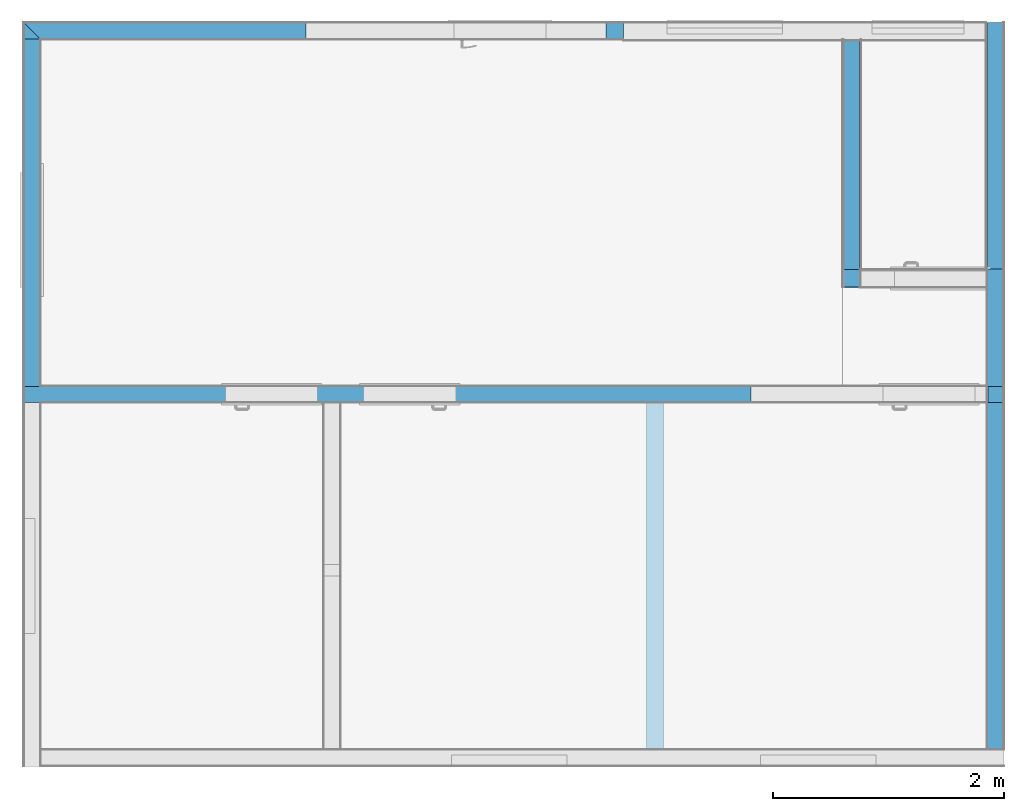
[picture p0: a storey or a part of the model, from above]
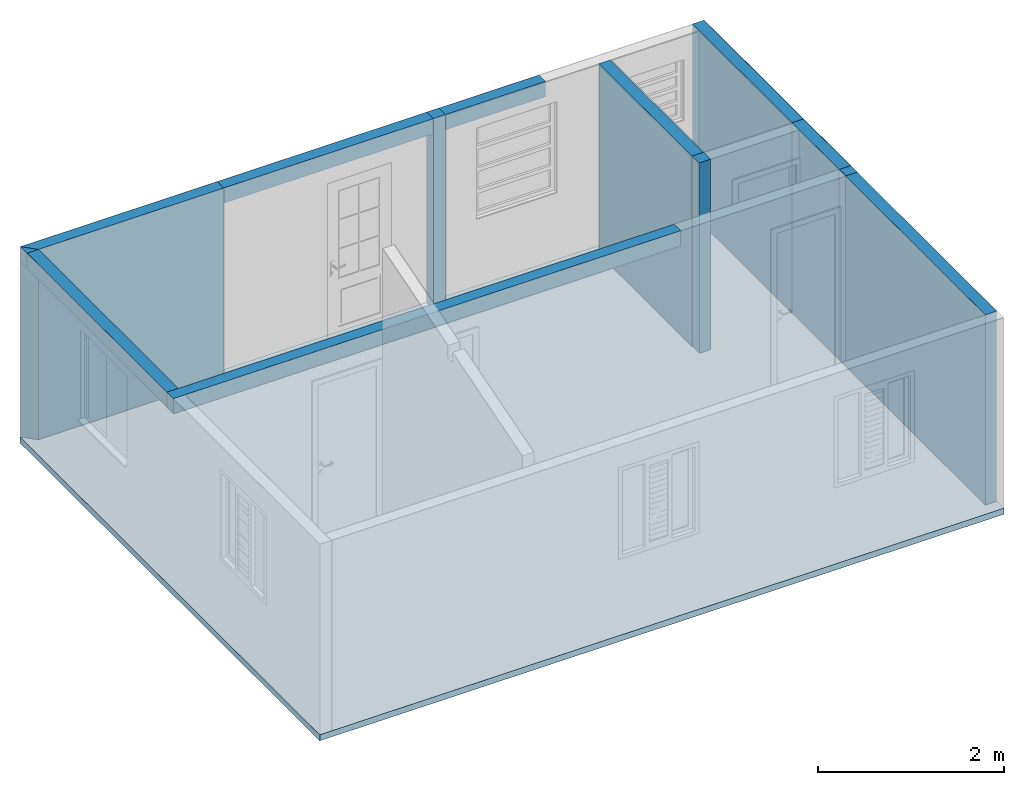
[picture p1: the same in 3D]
Properties of the parts of a building model (IFC2X3), part 1 of 6

# File
Description: ViewDefinition [CoordinationView_V2.0, QuantityTakeOffAddOnView], Option [Elements to export: Entire project], Option [Partial Structure Display: Entire Model], Option [IFC Domain: All], Option [Structural Function: All Elements], Option [Convert Grid elements: On], Option [Convert IFC Annotations and Archicad 2D elements: Off], Option [Convert 2D symbols of Doors and Windows: Off], Option [Export geometries that Participates in Collision Detection only: Off], Option [Split complex elements: On], Option [Elements in Solid Element Operations: Extruded/revolved], Option [Elements with junctions: Extruded/revolved without junctions], Option [IFC Model position: Survey Point and Project Origin], Option [Curtain Wall export mode: Container Element], Option [Railing export mode: Single Element], Option [Stair export mode: Container Element], Option [Properties To Export: All properties], Option [Space containment: Off], Option [Geometry to type objects: Off], Option [Element Properties: Visible Only], Option [Building Material Properties: On], Option [Element Parameters: All], Option [Component Parameters: All], Option [IFC Base Quantities: On], Option [Door Window Parameters: On], Option [IFC Space boundaries: Off], Option [Archicad Zone Categories as IFC Space classification data: On], Option [Element Classifications: On]
File name: C:\Users\jplen\Desktop\Modelagem e projeção de custos HIS\Desenvolvimento\CDHU\Casa CDHU\Modelagem - Casa CDHU - Estufamento 1.ifc
Time: 2024-10-02T12:29:50
Author: Architect
Organization: Building Designer Office
Written by: DDS_IFC v3.0
Made in: IFC file generated by Graphisoft Archicad 27.0.0 BRA FULL Windows version (IFC add-on version: 3001 BRA FULL).
Authorization: The authorising person

# IfcSite, Local
RefLatitude: -23, -32, 0, 0; RefLongitude: -46, -38, 0, 0; RefElevation: 0 mm
BaseQuantities - GrossPerimeter: 0 mm; GrossArea: 0 m2

# IfcBuilding, Construção
BaseQuantities - GrossFloorArea: 52.3119 m2

# IfcBuildingStorey (3)
In: Construção
Name | Elevation (mm) | NetHeight (mm) = GrossHeight (mm) = Height (mm) | GrossFloorArea (m2)
Cobertura | 2500 | 2500 | 0
Pavimento Térreo | 0 | 2500 | 52.3119
Fundação | -280 | 280 | 0

# IfcSpace: Circulação, 05
In: Pavimento Térreo
Type - ElementType: INTERNAL; PredefinedType: USERDEFINED
LongName: Hall; InteriorOrExteriorSpace: INTERNAL; Classification: Espaço Residencial (Classificação Archicad); 4A 19 04 10 Circulação (NBR 15965-6 4A); CIR Circulação
Pset_SpaceCommon - Category: Circulação
AC_Pset_Selo_de_Zona_01_27 - Tamanho Texto Marcador 1(Padrão): 3; Estilo Texto Marcador 1(Padrão): 0; Alinhamento Texto Marcador 1 (padrão): 1; Espaço entre Linhas Texto Marcador 1 (padrão): 1; Fator de Largura do Caractere Texto Marcador 1 (padrão): 1; Espaçamento do Caractere Texto Marcador 1 (padrão): 1; Caneta Texto Marcador 1(Padrão): Texto - Cotas; Tipo Fonte 1: Arial Ocidental; Nome de Zona (ROOM_NAME): Hall; Número da Zona: 04; Área Medida (ROOM_AREA): 1.071; Nº do Todos os Cantos: 4; Nº dos Cantos Côncavos: 0; Área da Superfície das Paredes do Perímetro: 5.026; Área da Superfície das Portas: 3.36; Área da Superfície das Janelas: 0; Área Útil Medida: 1.071; Área da Parede Extraída: 0; Área de Parede Cortina Extraída: 0; Área da Coluna Extraída: 0; Área Trama Extraída: 0; Áreas Baixas Extraídas: 0; Área Total Extraída: 0; Área Reduzida: 1.071; Factor Área Zona: 1; Área Calculada (ROOM_CALC_AREA): 1.071; Volume (ROOM_VOLUME): 2.6775; Área da Superfície das Bordas: 10.55; Área da Superfície do Topo: 1.071; Área da Superfície do Fundo: 1.071; Área de Superfície do Topo do Telhado: 0; Área de Superfície da Base do Telhado: 0; Área de Superfície no Topo da Laje: 0; Área de Superfície no Fundo da Laje: 0; Área da Superfície da Viga no Topo: 0; Superfície da Viga na Base: 0; Área da Superfície do Topo das Inserções da Parede: 0; Superfície de Trás das Inserções da Parede: 0; Área de Superfície do Lado das Inserções da Parede: 0; Polígono Zona (Bruto, Livre): 0; Sensível à Escala: yes; Escala Editada: 2; Mostrar Moldura: no; Caneta Moldura: Zonas - Molduras; Linhas entre Detalhes: yes; Número de Ordens: 2; 1.: 2; 2.: 4; 3.: 1; 4.: 1; 5.: 1; 6.: 1; 7.: 1; 8.: 1; 9.: 1; 10.: 1; 11.: 1; 12.: 1; 13.: 1; 14.: 1; Usar Categoria como Nome (cn_zn): no; Justificar para Subtexto (bZoneNameAllign): no; Sobrepor Formato do Texto Nome da Zona: yes; Tipo Fonte (fonttypeZoneName): Arial; Estilo de Fonte Nome da Zona: 1; Caneta Texto (zonapen): Zonas - Textos; Caneta Texto (zonapen_int): 54; Moldura (bFrameName): no; Mostrar ID como...: 2; Sobrepor Formato do Texto ID da Zona: yes; Tipo Fonte (fonttypeZoneID): Arial; Estilo de Fonte ID da Zona: 0; Caneta Texto (fontpenZoneID): Zonas - Textos; Caneta Texto (fontpenZoneID_int): 54; Moldura (bFrameZoneID): yes; Sobrepor Formato do Texto Número da Zona: yes; Tipo Fonte (zonofont): Arial; Estilo de Fonte Número da Zona: 1; Caneta Texto (zonopen): Zonas - Textos; Caneta Texto (zonopen_int): 54; Moldura (bFrameNum): yes; Número do Compartimento (bEnableZone1CustomText2): no; Prefixo (prefixRoomNumber): RN:; Sobrepor Formato Texto Número do Compartimento: yes; Tipo Fonte (fonttypeRoomNumber): Arial; Estilo de Fonte Número Compartimento: 0; Caneta Texto (roomNumberPen): Documentação - Geral; Caneta Texto (roomNumberPen_int): 5; Moldura (bFrameRoomNumber): yes; Ordem Dados (sOrderNameandNumber): Primeiro Número da Zona; Ordem Dados (iOrderNameandNumber): 1; Usar Categoria como Nome (bByCategoryNameAndNumber): no; Justificar para Subtexto (bNameAllignNameAndNumber): no; Sobrepor Formato do Texto Nome e Número da Zona: yes; Tipo Fonte (fonttypeNameAndNumber): Arial; Estilo de Fonte Nome e Número da Zona: 1; Caneta Texto (nameAndNumberPen): Zonas - Textos; Caneta Texto (nameAndNumberPen_int): 54; Moldura (bFrameNameAndNumber): yes; Sobrepor Formato do Texto Área Medida: yes; Texto (GrossAreaText): A:; Tipo Fonte (GrossAreaFont): Arial; Estilo de Fonte Área Medida: 0; Caneta Texto (GrossAreaPen): Zonas - Textos; Caneta Texto (GrossAreaPen_int): 54; Moldura (bFrameGrossArea): no; Calcular Área DIN: no; Texto (areatext): AC:; Sobrepor Formato do Texto Área Calculada: yes; Tipo Fonte (areafont): Arial; Estilo de Fonte Área Calculada: 0; Caneta Texto (areapen): Zonas - Textos; Caneta Texto (areapen_int): 54; Moldura (bFrameArea): yes; Tipo Pavimento: <tipo pavimento>; Sobrepor Formato do Texto Piso: yes; Tipo Fonte (codefont): Arial; Estilo de Fonte Piso: 0; Caneta Texto (codepen): Zonas - Textos; Caneta Texto (codepen_int): 54; Moldura (bFrameCode): yes; Número do Compartimento (bEnableZone1SurfaceCode): no; Mostrar Tipo de Acabamento por (sComponentSurfaceCode): Código Personalizado; Mostrar Tipo de Acabamento por (iComponentSurfaceCode): 1; Superfície Piso: Tapete - 01; Superfície da Base: Tapete - 01; Superfície Parede: Pintura - Branco Polido; Superfície teto: Pintura - Branco Polido; Sobrepor Formato do Texto Código da Superfície: yes; Tipo Fonte (fonttypeSurfaceCode): Arial; Estilo de Fonte Código da Superfície: 0; Caneta Texto (surfaceCodepen): Documentação - Geral; Caneta Texto (surfaceCodepen_int): 5; Moldura (bFrameSurfaceCode): yes; Sobrepor Formato do Texto Perímetro: yes; Texto (peritext): P:; Tipo Fonte (perifont): Arial; Estilo de Fonte Perímetro: 0; Caneta Texto (peripen): Zonas - Textos; Caneta Texto (peripen_int): 54; Moldura (bFramePeri): yes; Tipo de Altura: 1; Texto (ceiltext): Alt:; Sobrepor Formato do Texto Altura do Teto: yes; Tipo Fonte (ceilhfont): Arial; Estilo de Fonte Altura Teto: 0; Caneta Texto (ceilhpen): Zonas - Textos; Caneta Texto (ceilhpen_int): 54; Moldura (bFrameCeil): yes; Texto (VolumeText): V:; Sobrepor Formato do Texto Volume: yes; Tipo Fonte (VolumeFont): Arial; Estilo Fonte Volume: 0; Caneta Texto (VolumePen): Zonas - Textos; Caneta Texto (VolumePen_int): 54; Moldura (bFrameVolume): yes; Sobrepor Formato do Texto Classificação e Propriedades: yes; Tipo Fonte (AdditionalTagsFont): Arial; Estilo de Fonte Classificação e Propriedades: 0; Caneta Texto (AdditionalTagsPen): Zonas - Textos; Caneta Texto (AdditionalTagsPen_int): 54; Moldura (bFrameAdditionalTags): yes; Parâmetros Selecionados: 1; Exibir Dados por: 1; 1. Linha Exibir Nome Parâmetro como: 1; 2. Linha Exibir Nome Parâmetro como: 1; 3. Linha Exibir Nome Parâmetro como: 1; 4. Linha Exibir Nome Parâmetro como: 1; 5. Linha Exibir Nome Parâmetro como: 1; 6. Linha Exibir Nome Parâmetro como: 1; 7. Linha Exibir Nome Parâmetro como: 1; 8. Linha Exibir Nome Parâmetro como: 1; 9. Linha Exibir Nome Parâmetro como: 1; 10. Linha Exibir Nome Parâmetro como: 1; 11. Linha Exibir Nome Parâmetro como: 1; 12. Linha Exibir Nome Parâmetro como: 1; 13. Linha Exibir Nome Parâmetro como: 1; 14. Linha Exibir Nome Parâmetro como: 1; 15. Linha Exibir Nome Parâmetro como: 1; 16. Linha Exibir Nome Parâmetro como: 1; 17. Linha Exibir Nome Parâmetro como: 1; 18. Linha Exibir Nome Parâmetro como: 1; 19. Linha Exibir Nome Parâmetro como: 1; 20. Linha Exibir Nome Parâmetro como: 1; Definir Ocupação por Área: yes; Área por Pessoa em metros quad.: 1; Área por Pessoa em pés quad.: 10.7639; Número de Ocupantes Adicionais: 0; Número de Ocupantes: 3; Ocupação (result_occupancy): 1; Prefixo (gs_occupancy_text): Ocupação:; Sobrepor Formato do Texto Ocupação: yes; Tipo Fonte (gs_type_font_occupancy): Arial; Estilo de Fonte Ocupação: 0; Caneta Texto (gs_pen_font_occupancy): Zonas - Textos; Caneta Texto (gs_pen_font_occupancy_int): 54; Moldura (gs_show_frame_occupancy): yes; Prefixo (prefixCustomText): Nota:; Sobrepor Formato do Texto Personalizado: yes; Tipo Fonte (fonttypeCustomText): Arial; Estilo de Fonte Texto Personalizado: 0; Caneta Texto (customTextPen): Zonas - Textos; Caneta Texto (customTextPen_int): 54; Moldura (bFrameCustomText): yes; Unidade Área Zona (bEnableTsuboArea): no; Unidade Área Zona (iAreaUnit): 1; Decimais: 2; Ponto Médio Pontos-Quentes: yes; Ponto de Inserção: 5; Largura Selo da Zona: 2; Valor Largura: 30; Defina o tamanho da fonte por: 2; Tamanho de Fonte para Texto Detalhe (mm): 3; Tamanho de Fonte para Texto Detalhe (pt): 8.50394; Justificação Texto de Detalhe: 2; Tipo de Trama: Trama Vazia; Caneta da Trama: Zonas - Trama de Superfície; Caneta do Fundo da Trama: Transparente; Custo/Total: 0; Custo/m2: 0
AC_Pset_RenovationAndPhasing - Renovation Status: Existing
BaseQuantities - Height: 2500 mm; FinishCeilingHeight: 2500 mm; FinishFloorHeight: 0 mm; ClearHeight: 2500 mm; GrossFloorArea: 1.071 m2; NetFloorArea: 1.071 m2; SpaceNetFloorAreaBOMA: 1.071 m2; SpaceUsableFloorAreaBOMA: 1.071 m2; GrossCeilingArea: 1.071 m2; NetCeilingArea: 1.071 m2; GrossWallArea: 0.4 m2; NetWallArea: 0.4 m2; GrossPerimeter: 4220 mm; NetPerimeter: 4220 mm; GrossVolume: 2.6775 m3; NetVolume: 2.6775 m3
AC_Equantity_Selo_de_Zona_01_27 - Perímetro: 4220 mm; Perímetro dos Vãos: 0 mm; Comprimento das Paredes Perímetro: 3360 mm; Largura Combinada das Portas: 1600 mm; Largura Combinada das Janelas: 0 mm; Nível do Piso: 0 mm; Espessura do Subpiso: 0 mm; Altura: 2500 mm; Perímetro Útil: 4220 mm; Tamanho de Fonte para Texto de Detalhe (modelo): 300 mm
ArchiCADProperties - Superfície: Vidro - Azul; Superfície Uniforme: yes; Nome Zona: Hall; Número da Zona: 04; Categoria de Zona: 0; Código da Categoria da Zona: CIR; Elemento(s) 3D relacionado(s): P02; P05; Parede-03 - Trecho 2; Parede-08; ID do Elemento: Zona-004; ID do Elemento e Associação: Zona-004; Vegetal: ARQ - Zona; Nome de Item de Biblioteca: Selo de Zona 01 27; Nome da Zona Relacionada: Hall; Número da Zona Relacionada: 04; Protegido: no; Nome Piso de Origem: Pavimento Térreo; Número Piso de Origem: 0; Tipo de Elemento: Zona; Ponto de Vínculo do Piso Absoluto: Cobertura; Ponto de Vínculo do Piso Relativo: Original + 1; Vínculo Superior do Piso: Original + 1 (Cobertura); ID Pai: Zona-004; Superfícies (Todas): Vidro - Azul; Trama em Vista: Trama Vazia; Nome das Opções de Projeto: Modelo Principal; Nome do Conjunto de Opções de Projeto: Modelo Principal; Mostrar em Filtro de Renovação: Todos os Filtros Relevantes; Estado de Renovação: Existente; Estado das Opções de Projeto: Modelo Principal; Conjunto de Opções de Projeto: Modelo Principal
ArchiCADQuantities - Número de Vigas: 0; Número de Pilares: 0; Número de Portas: 0; Número de Luminárias: 0; Número de Objetos: 0; Número de Janelas: 0; Número de Itens de Paredes: 1; Área Calculada: 1.071 m2; Área Medida: 1.071 m2; Área de Superfície das Janelas: 0 m2; Área de Superfície das Portas: 0 m2; Área de Superfície das Paredes: 0.4 m2; Largura Portas: 0 mm; Largura Janelas: 0 mm; Perímetro Paredes: 3360 mm; Perímetro Útil da Zona: 4220 mm; Perímetro Bruto Zona: 4220 mm; Espessura de Pavimento: 0 mm; Redução de área: 1 m2; Extrair Área da Base do Pilar: 0 m2; Extrair Área da Trama: 0 m2; Área Baixa Extraída: 0 m2; Extrair Área da Base da Parede: 0 m2; Área Líquida Medida: 1.071 m2; Número dos Cantos Côncavos: 0; Número de Cantos: 4; Área Reduzida: 1.071 m2; Área Total Extraída: 0 m2; Inserção da Parede no Lado Posterior da Área de Superfície: 0 m2; Inserção da Parede no Lado da Área de Superfície: 0 m2; Inserção da Parede na Área da Superfície do Topo: 0 m2; Área Extraída da Parede Cortina: 0 m2; Área: 1.071 m2; Altura: 2500 mm; Volume (Líquido): 2.6775 m3; Elevação à Origem do Projeto: 0 mm; Elevação ao 1º Nível de Referência: 0 mm; Elevação ao 2º Nível de Referência: 0 mm; Elevação ao Nível do Mar: 0 mm; Elevação ao Piso: 0 mm; Afastamento do Piso de Origem: 0 mm; Afastamento do Topo: 0 mm; Perímetro Furos da Planta: 0 mm; Elevação do Topo ao Primeiro Nível de Referência: 2500 mm; Elevação do Topo Ao Piso de Origem: 2500 mm; Elevação do Topo À Cota Zero: 2500 mm; Elevação do Topo Ao Nível do Mar: 2500 mm; Elevação do Topo Ao Segundo Nível de Referência: 2500 mm; Elevação da Base Ao Primeiro Nível de Referência: 0 mm; Elevação da Base Ao Piso de Origem: 0 mm; Elevação da Base À Cota Zero: 0 mm; Elevação da Base Ao Nível do Mar: 0 mm; Elevação da Base Ao Segundo Nível de Referência: 0 mm; Área da Superfície do Topo (Líquida): 1.071 m2; Área da Superfície da Borda (Líquida): 10.55 m2; Área da Superfície da Base (Líquida): 1.071 m2

# IfcSpace: Área Privativa (6)
In: Pavimento Térreo
Type - ElementType: INTERNAL; PredefinedType: USERDEFINED
InteriorOrExteriorSpace: INTERNAL
Pset_SpaceCommon - Category: Área Privativa
ArchiCADProperties - Superfície: Vidro - Azul; Superfície Uniforme: yes; Categoria de Zona: 0; Código da Categoria da Zona: PRIV; Vegetal: ARQ - Zona; Nome de Item de Biblioteca: Selo de Zona 01 27; Protegido: no; Nome Piso de Origem: Pavimento Térreo; Número Piso de Origem: 0; Tipo de Elemento: Zona; Ponto de Vínculo do Piso Absoluto: Cobertura; Ponto de Vínculo do Piso Relativo: Original + 1; Vínculo Superior do Piso: Original + 1 (Cobertura); Superfícies (Todas): Vidro - Azul; Trama em Vista: Trama Vazia; Nome das Opções de Projeto: Modelo Principal; Nome do Conjunto de Opções de Projeto: Modelo Principal; Mostrar em Filtro de Renovação: Todos os Filtros Relevantes; Estado de Renovação: Existente; Estado das Opções de Projeto: Modelo Principal; Conjunto de Opções de Projeto: Modelo Principal
AC_Pset_RenovationAndPhasing - Renovation Status: Existing
BaseQuantities - Height: 2500 mm; FinishCeilingHeight: 2500 mm; FinishFloorHeight: 0 mm; ClearHeight: 2500 mm
ArchiCADQuantities - Número de Pilares: 0; Número de Luminárias: 0; Número de Objetos: 0; Espessura de Pavimento: 0 mm; Redução de área: 1 m2; Extrair Área da Base do Pilar: 0 m2; Extrair Área da Trama: 0 m2; Área Baixa Extraída: 0 m2; Extrair Área da Base da Parede: 0 m2; Área Total Extraída: 0 m2; Inserção da Parede no Lado Posterior da Área de Superfície: 0 m2; Inserção da Parede no Lado da Área de Superfície: 0 m2; Inserção da Parede na Área da Superfície do Topo: 0 m2; Área Extraída da Parede Cortina: 0 m2; Altura: 2500 mm; Elevação à Origem do Projeto: 0 mm; Elevação ao 1º Nível de Referência: 0 mm; Elevação ao 2º Nível de Referência: 0 mm; Elevação ao Nível do Mar: 0 mm; Elevação ao Piso: 0 mm; Afastamento do Piso de Origem: 0 mm; Afastamento do Topo: 0 mm; Perímetro Furos da Planta: 0 mm; Elevação do Topo ao Primeiro Nível de Referência: 2500 mm; Elevação do Topo Ao Piso de Origem: 2500 mm; Elevação do Topo À Cota Zero: 2500 mm; Elevação do Topo Ao Nível do Mar: 2500 mm; Elevação do Topo Ao Segundo Nível de Referência: 2500 mm; Elevação da Base Ao Primeiro Nível de Referência: 0 mm; Elevação da Base Ao Piso de Origem: 0 mm; Elevação da Base À Cota Zero: 0 mm; Elevação da Base Ao Nível do Mar: 0 mm; Elevação da Base Ao Segundo Nível de Referência: 0 mm
AC_Equantity_Selo_de_Zona_01_27 - Perímetro dos Vãos: 0 mm; Nível do Piso: 0 mm; Espessura do Subpiso: 0 mm; Altura: 2500 mm; Tamanho de Fonte para Texto de Detalhe (modelo): 300 mm
AC_Pset_Selo_de_Zona_01_27 - Tamanho Texto Marcador 1(Padrão): 3; Estilo Texto Marcador 1(Padrão): 0; Alinhamento Texto Marcador 1 (padrão): 1; Espaço entre Linhas Texto Marcador 1 (padrão): 1; Fator de Largura do Caractere Texto Marcador 1 (padrão): 1; Espaçamento do Caractere Texto Marcador 1 (padrão): 1; Caneta Texto Marcador 1(Padrão): Texto - Cotas; Tipo Fonte 1: Arial Ocidental; Área da Parede Extraída: 0; Área de Parede Cortina Extraída: 0; Área da Coluna Extraída: 0; Área Trama Extraída: 0; Áreas Baixas Extraídas: 0; Área Total Extraída: 0; Factor Área Zona: 1; Área de Superfície do Topo do Telhado: 0; Área de Superfície da Base do Telhado: 0; Área de Superfície no Topo da Laje: 0; Área de Superfície no Fundo da Laje: 0; Área da Superfície da Viga no Topo: 0; Superfície da Viga na Base: 0; Área da Superfície do Topo das Inserções da Parede: 0; Superfície de Trás das Inserções da Parede: 0; Área de Superfície do Lado das Inserções da Parede: 0; Polígono Zona (Bruto, Livre): 0; Sensível à Escala: yes; Escala Editada: 2; Mostrar Moldura: no; Caneta Moldura: Zonas - Molduras; Linhas entre Detalhes: yes; Número de Ordens: 2; 1.: 2; 2.: 4; 3.: 1; 4.: 1; 5.: 1; 6.: 1; 7.: 1; 8.: 1; 9.: 1; 10.: 1; 11.: 1; 12.: 1; 13.: 1; 14.: 1; Usar Categoria como Nome (cn_zn): no; Justificar para Subtexto (bZoneNameAllign): no; Sobrepor Formato do Texto Nome da Zona: yes; Tipo Fonte (fonttypeZoneName): Arial; Estilo de Fonte Nome da Zona: 1; Caneta Texto (zonapen): Zonas - Textos; Caneta Texto (zonapen_int): 54; Moldura (bFrameName): no; Mostrar ID como...: 2; Sobrepor Formato do Texto ID da Zona: yes; Tipo Fonte (fonttypeZoneID): Arial; Estilo de Fonte ID da Zona: 0; Caneta Texto (fontpenZoneID): Zonas - Textos; Caneta Texto (fontpenZoneID_int): 54; Moldura (bFrameZoneID): yes; Sobrepor Formato do Texto Número da Zona: yes; Tipo Fonte (zonofont): Arial; Estilo de Fonte Número da Zona: 1; Caneta Texto (zonopen): Zonas - Textos; Caneta Texto (zonopen_int): 54; Moldura (bFrameNum): yes; Número do Compartimento (bEnableZone1CustomText2): no; Prefixo (prefixRoomNumber): RN:; Sobrepor Formato Texto Número do Compartimento: yes; Tipo Fonte (fonttypeRoomNumber): Arial; Estilo de Fonte Número Compartimento: 0; Caneta Texto (roomNumberPen): Documentação - Geral; Caneta Texto (roomNumberPen_int): 5; Moldura (bFrameRoomNumber): yes; Ordem Dados (sOrderNameandNumber): Primeiro Número da Zona; Ordem Dados (iOrderNameandNumber): 1; Usar Categoria como Nome (bByCategoryNameAndNumber): no; Justificar para Subtexto (bNameAllignNameAndNumber): no; Sobrepor Formato do Texto Nome e Número da Zona: yes; Tipo Fonte (fonttypeNameAndNumber): Arial; Estilo de Fonte Nome e Número da Zona: 1; Caneta Texto (nameAndNumberPen): Zonas - Textos; Caneta Texto (nameAndNumberPen_int): 54; Moldura (bFrameNameAndNumber): yes; Sobrepor Formato do Texto Área Medida: yes; Texto (GrossAreaText): A:; Tipo Fonte (GrossAreaFont): Arial; Estilo de Fonte Área Medida: 0; Caneta Texto (GrossAreaPen): Zonas - Textos; Caneta Texto (GrossAreaPen_int): 54; Moldura (bFrameGrossArea): no; Calcular Área DIN: no; Texto (areatext): AC:; Sobrepor Formato do Texto Área Calculada: yes; Tipo Fonte (areafont): Arial; Estilo de Fonte Área Calculada: 0; Caneta Texto (areapen): Zonas - Textos; Caneta Texto (areapen_int): 54; Moldura (bFrameArea): yes; Tipo Pavimento: <tipo pavimento>; Sobrepor Formato do Texto Piso: yes; Tipo Fonte (codefont): Arial; Estilo de Fonte Piso: 0; Caneta Texto (codepen): Zonas - Textos; Caneta Texto (codepen_int): 54; Moldura (bFrameCode): yes; Número do Compartimento (bEnableZone1SurfaceCode): no; Mostrar Tipo de Acabamento por (sComponentSurfaceCode): Código Personalizado; Mostrar Tipo de Acabamento por (iComponentSurfaceCode): 1; Superfície Piso: Tapete - 01; Superfície da Base: Tapete - 01; Superfície Parede: Pintura - Branco Polido; Superfície teto: Pintura - Branco Polido; Sobrepor Formato do Texto Código da Superfície: yes; Tipo Fonte (fonttypeSurfaceCode): Arial; Estilo de Fonte Código da Superfície: 0; Caneta Texto (surfaceCodepen): Documentação - Geral; Caneta Texto (surfaceCodepen_int): 5; Moldura (bFrameSurfaceCode): yes; Sobrepor Formato do Texto Perímetro: yes; Texto (peritext): P:; Tipo Fonte (perifont): Arial; Estilo de Fonte Perímetro: 0; Caneta Texto (peripen): Zonas - Textos; Caneta Texto (peripen_int): 54; Moldura (bFramePeri): yes; Tipo de Altura: 1; Texto (ceiltext): Alt:; Sobrepor Formato do Texto Altura do Teto: yes; Tipo Fonte (ceilhfont): Arial; Estilo de Fonte Altura Teto: 0; Caneta Texto (ceilhpen): Zonas - Textos; Caneta Texto (ceilhpen_int): 54; Moldura (bFrameCeil): yes; Texto (VolumeText): V:; Sobrepor Formato do Texto Volume: yes; Tipo Fonte (VolumeFont): Arial; Estilo Fonte Volume: 0; Caneta Texto (VolumePen): Zonas - Textos; Caneta Texto (VolumePen_int): 54; Moldura (bFrameVolume): yes; Sobrepor Formato do Texto Classificação e Propriedades: yes; Tipo Fonte (AdditionalTagsFont): Arial; Estilo de Fonte Classificação e Propriedades: 0; Caneta Texto (AdditionalTagsPen): Zonas - Textos; Caneta Texto (AdditionalTagsPen_int): 54; Moldura (bFrameAdditionalTags): yes; Parâmetros Selecionados: 1; Exibir Dados por: 1; 1. Linha Exibir Nome Parâmetro como: 1; 2. Linha Exibir Nome Parâmetro como: 1; 3. Linha Exibir Nome Parâmetro como: 1; 4. Linha Exibir Nome Parâmetro como: 1; 5. Linha Exibir Nome Parâmetro como: 1; 6. Linha Exibir Nome Parâmetro como: 1; 7. Linha Exibir Nome Parâmetro como: 1; 8. Linha Exibir Nome Parâmetro como: 1; 9. Linha Exibir Nome Parâmetro como: 1; 10. Linha Exibir Nome Parâmetro como: 1; 11. Linha Exibir Nome Parâmetro como: 1; 12. Linha Exibir Nome Parâmetro como: 1; 13. Linha Exibir Nome Parâmetro como: 1; 14. Linha Exibir Nome Parâmetro como: 1; 15. Linha Exibir Nome Parâmetro como: 1; 16. Linha Exibir Nome Parâmetro como: 1; 17. Linha Exibir Nome Parâmetro como: 1; 18. Linha Exibir Nome Parâmetro como: 1; 19. Linha Exibir Nome Parâmetro como: 1; 20. Linha Exibir Nome Parâmetro como: 1; Definir Ocupação por Área: yes; Área por Pessoa em metros quad.: 1; Área por Pessoa em pés quad.: 10.7639; Número de Ocupantes Adicionais: 0; Número de Ocupantes: 3; Prefixo (gs_occupancy_text): Ocupação:; Sobrepor Formato do Texto Ocupação: yes; Tipo Fonte (gs_type_font_occupancy): Arial; Estilo de Fonte Ocupação: 0; Caneta Texto (gs_pen_font_occupancy): Zonas - Textos; Caneta Texto (gs_pen_font_occupancy_int): 54; Moldura (gs_show_frame_occupancy): yes; Prefixo (prefixCustomText): Nota:; Sobrepor Formato do Texto Personalizado: yes; Tipo Fonte (fonttypeCustomText): Arial; Estilo de Fonte Texto Personalizado: 0; Caneta Texto (customTextPen): Zonas - Textos; Caneta Texto (customTextPen_int): 54; Moldura (bFrameCustomText): yes; Unidade Área Zona (bEnableTsuboArea): no; Unidade Área Zona (iAreaUnit): 1; Decimais: 2; Ponto Médio Pontos-Quentes: yes; Ponto de Inserção: 5; Largura Selo da Zona: 2; Valor Largura: 30; Defina o tamanho da fonte por: 2; Tamanho de Fonte para Texto Detalhe (mm): 3; Tamanho de Fonte para Texto Detalhe (pt): 8.50394; Justificação Texto de Detalhe: 2; Tipo de Trama: Trama Vazia; Caneta da Trama: Zonas - Trama de Superfície; Caneta do Fundo da Trama: Transparente; Custo/Total: 0; Custo/m2: 0
Name | LongName = Nome Zona = Nome da Zona Relacionada = Nome de Zona (ROOM_NAME) | Classification | ArchiCADProperties, Número da Zona = Número da Zona Relacionada = AC_Pset_Selo_de_Zona_01_27, Número da Zona | Elemento(s) 3D relacionado(s) | ID do Elemento = ID do Elemento e Associação = ID Pai | GrossFloorArea (m2) = NetFloorArea (m2) = SpaceNetFloorAreaBOMA (m2) = SpaceUsableFloorAreaBOMA (m2) = GrossCeilingArea (m2) = NetCeilingArea (m2) = Área Calculada (m2) = Área Medida (m2) = Área Líquida Medida (m2) = ArchiCADQuantities, Área Reduzida (m2) = Área (m2) = Área da Superfície do Topo (Líquida) (m2) = Área da Superfície da Base (Líquida) (m2) = Área Medida (ROOM_AREA) = Área Útil Medida = AC_Pset_Selo_de_Zona_01_27, Área Reduzida = Área Calculada (ROOM_CALC_AREA) = Área da Superfície do Topo = Área da Superfície do Fundo | GrossWallArea (m2) | NetWallArea (m2) = Área de Superfície das Paredes (m2) | GrossPerimeter (mm) = NetPerimeter (mm) = Perímetro Útil da Zona (mm) = Perímetro Bruto Zona (mm) = Perímetro (mm) = Perímetro Útil (mm) | GrossVolume (m3) = NetVolume (m3) = Volume (Líquido) (m3) = Volume (ROOM_VOLUME) | Número de Vigas | Número de Portas | Número de Janelas | Número de Itens de Paredes | Área de Superfície das Janelas (m2) | Área de Superfície das Portas (m2) | Largura Portas (mm) | Largura Janelas (mm) | Perímetro Paredes (mm) = Comprimento das Paredes Perímetro (mm) | Número dos Cantos Côncavos = Nº dos Cantos Côncavos | Número de Cantos = Nº do Todos os Cantos | Área da Superfície da Borda (Líquida) (m2) = Área da Superfície das Bordas | Largura Combinada das Portas (mm) | Largura Combinada das Janelas (mm) | Área da Superfície das Paredes do Perímetro | Área da Superfície das Portas | Área da Superfície das Janelas | Ocupação (result_occupancy)
04 | Banheiro | 4A 19 04 07 Banheiro residencial (NBR 15965-6 4A); Espaço Residencial (Classificação Archicad); PRIV Área Privativa | 03 | P06 | Zona-003 | 2.13068 | 15.2805 | 12.9815 | 6112.2 | 5.3267 | 0 | 1 | 1 | 4 | 0.64 | 1.659 | 790 | 800 | 6120.98 | 0 | 4 | 15.2805 | 0 | 0 | 12.9545 | 0 | 0 | 2
03 | Dormitório 2 | Espaço Residencial (Classificação Archicad); PRIV Área Privativa; 4A 19 01 01 Dormitório (NBR 15965-6 4A) | 02 | P02 | Zona-002 | 7.95 | 20.75 | 17.87 | 11300 | 19.875 | 0 | 1 | 1 | 3 | 1.2 | 1.68 | 800 | 1000 | 12000 | 0 | 4 | 28.25 | 800 | 1000 | 27.1128 | 1.68 | 1.2 | 7
01 | Dormitório 1 | Espaço Residencial (Classificação Archicad); PRIV Área Privativa; 4A 19 01 01 Dormitório (NBR 15965-6 4A) | 01 | P01 | Zona-001 | 7.35 | 27.22 | 24.34 | 10900 | 18.375 | 0 | 1 | 1 | 4 | 1.2 | 1.68 | 800 | 1000 | 12000 | 0 | 4 | 27.25 | 800 | 1000 | 27.1128 | 1.68 | 1.2 | 7
06 | Cozinha | Espaço Residencial (Classificação Archicad); PRIV Área Privativa; 4A 19 01 25 Cozinha (NBR 15965-6 4A) | 05 | P04; Zona-006 | Zona-005 | 5.5426 | 10.0847 | 8.88475 | 9460 | 13.8565 | 0 | 0 | 1 | 3 | 1.2 | 0 | 0 | 1000 | 4730 | 0 | 4 | 23.65 | 0 | 0 | 10.625 | 0 | 0 | 5 | ArchiCADProperties - Zonas em Colisão: Sala de estar
07 | Sala de estar | Espaço Residencial (Classificação Archicad); PRIV Área Privativa; 4A 19 01 07 Sala de Estar (NBR 15965-6 4A) | 06 | P04; Parede-01; Parede-04 - Trecho 1; Parede-04 - Trecho 2; V01; Zona-005 | Zona-006 | 15.291 | 0 | 0 | 19906.8 | 38.2274 | 2 | 0 | 0 | 0 | 0 | 0 | 0 | 0 | 7890 | 1 | 6 | 49.767 | 800 | 1000 | 16.838 | 1.68 | 1.2 | 15 | ArchiCADProperties - Zonas em Colisão: Cozinha
02 | Dormitório 3 | Espaço Residencial (Classificação Archicad); PRIV Área Privativa; 4A 19 01 01 Dormitório (NBR 15965-6 4A) | 02 | P03; P04; Parede-03 - Trecho 3; Parede-05 | Zona-007 | 8.43 | 0 | 0 | 11620 | 21.075 | 2 | 0 | 0 | 0 | 0 | 0 | 0 | 0 | 12000 | 0 | 4 | 29.05 | 800 | 1000 | 27.1128 | 1.68 | 1.2 | 8

# IfcBeam: Concreto - Estrutural 140 x 200 (4)
In: Pavimento Térreo
Type - PredefinedType: BEAM
Description: Viga-externa-inloco-concreto_armado-20cm x 15cm; Classification: Viga (Classificação Archicad); 3E 12 06 02 00 Viga (NBR 15965-5 3E); Material: Concreto - Estrutural
Pset_ManufacturerTypeInformation - ProductionYear: DD/MM/YYYY
ArchiCADProperties - Corte Transversal da Viga: Retangular; Superfície Extremidade: Concreto - 03; Superfície Lado Esquerdo: Concreto - 03; Superfície Lado Direito: Concreto - 03; Ângulo de Inclinação da Viga: 0 deg; Geração Modelo Analítico Estrutural: yes; Membro Alongado Manualmente: no; Vegetal: EST - Viga; Material de Construção/ Composição / Perfil / Trama: Concreto - Estrutural; Material de Construção: Concreto - Estrutural; Protegido: no; Nome Piso de Origem: Pavimento Térreo; Número Piso de Origem: 0; Tipo de Elemento: Viga; Tipo: Básica; Materiais de Construção (Todos): Concreto - Estrutural; Superfícies (Todas): Concreto - 03; Trama em Vista: Trama Vazia; Ângulo de Inclinação: 0 deg; Número de Aberturas: 0; Superfície do Topo: Concreto - 03; Superfície da Base: Concreto - 03; Nome das Opções de Projeto: Modelo Principal; Nome do Conjunto de Opções de Projeto: Modelo Principal; Posição: Interior; Mostrar em Filtro de Renovação: Todos os Filtros Relevantes; Função Estrutural: Elemento Estrutural; Estado de Renovação: Existente; Estado das Opções de Projeto: Modelo Principal; Conjunto de Opções de Projeto: Modelo Principal
AC_Pset_RenovationAndPhasing - Renovation Status: Existing
Pset_BeamCommon - IsExternal: no; LoadBearing: yes; Reference: Concreto - Estrutural 140 x 200
Component Properties - Concreto - Estrutural, Tipo de Componente: Núcleo
Material Properties - Concreto - Estrutural, ThermalConductivity: 2.3; Concreto - Estrutural, SpecificHeatCapacity: 1000 J/kg/K; Concreto - Estrutural, MassDensity: 2300 kg/m3; Concreto - Estrutural, Embodied Energy: 1.92 (MJ/kg); Concreto - Estrutural, Embodied Carbon: 0.198 (kgCO₂/kg); Concreto - Estrutural, Name: Concreto - Estrutural; Concreto - Estrutural, ID: CON; Concreto - Estrutural, Participates in Collision Detection: yes
ArchiCADQuantities - Área da Superfície das Extremidades da Viga: 0.056 m2; Número Furo: 0; Área da Borda do Furo: 0 m2; Área de Superfície dos Furos: 0 m2; Volume Furos: 0 m3; Afastamento Eixo a partir do Centro: 0 mm; Altura: 200 mm; Largura: 140 mm; Elevação à Origem do Projeto: 2500 mm; Elevação ao 1º Nível de Referência: 2500 mm; Elevação ao 2º Nível de Referência: 2500 mm; Elevação ao Nível do Mar: 2500 mm; Elevação ao Piso: 2500 mm; Afastamento do Piso de Origem: 2500 mm; Elevação do Topo ao Primeiro Nível de Referência: 2500 mm; Elevação do Topo Ao Piso de Origem: 2500 mm; Elevação do Topo À Cota Zero: 2500 mm; Elevação do Topo Ao Nível do Mar: 2500 mm; Elevação do Topo Ao Segundo Nível de Referência: 2500 mm; Elevação da Base Ao Primeiro Nível de Referência: 2300 mm; Elevação da Base Ao Piso de Origem: 2300 mm; Elevação da Base À Cota Zero: 2300 mm; Elevação da Base Ao Nível do Mar: 2300 mm; Elevação da Base Ao Segundo Nível de Referência: 2300 mm; Altura do Corte Transversal no Topo/Terminação (perpendicular): 200 mm; Altura do Corte Transversal na Base/Início (perpendicular): 200 mm; Largura do Corte Transversal no Topo/Terminação (perpendicular): 140 mm; Largura do Corte Transversal na Base/Início (perpendicular): 140 mm; Altura do Corte Transversal no Topo/Terminação (corte): 200 mm; Altura do Corte Transversal na Base/Início (corte): 200 mm; Largura do Corte Transversal no Topo/Terminação (corte): 140 mm; Largura do Corte Transversal na Base/Início (corte): 140 mm; Área do Corte Transversal na Base/Início: 0.028 m2; Altura do Corte Transversal no Topo/Terminação: 0.028 m2; Número de Segmentos: 1
BaseQuantities - Width: 140 mm; Depth: 200 mm; CrossSectionArea: 0.028 m2
Component Quantities - Concreto - Estrutural, Espessura do Componente: 140 mm; Concreto - Estrutural, Altura do Componente Retangular: 200 mm; Concreto - Estrutural, Largura do Componente Retangular: 140 mm; Concreto - Estrutural, Área de Seção Transversal do Componente: 0.028 m2
Name | ID do Elemento = ID do Elemento e Associação = ID Pai | Nome da Zona Relacionada | Número da Zona Relacionada | Concreto - Estrutural, Carbono Incorporado | Concreto - Estrutural, Energia Incorporada (MJ) | Área da Superfície do Lado Esquerdo da Viga (Líquida) (m2) = Área da Superfície do Lado Direito da Viga (Líquida) (m2) = Concreto - Estrutural, Área de Componente Projetada (Líquida) (m2) = Concreto - Estrutural, Área de Componente Projetada (Bruta) (m2) | Comprimento Esquerda (mm) = Comprimento Direita (mm) = Comprimento 3D (mm) = Length (mm) | Área (m2) = Área da Superfície do Topo (Líquida) (m2) = Área da Superfície da Base (Líquida) (m2) | Volume (Líquido) (m3) = Volume (Condicional) (m3) = Volume (Bruto) (m3) = GrossVolume (m3) = NetVolume (m3) = Concreto - Estrutural, Volume Componente (Líquido) (m3) = Concreto - Estrutural, Volume do componente (Bruto) (m3) = Concreto - Estrutural, Volume Componente (Condicional) (m3) | Área da Superfície (m2) = TotalSurfaceArea (m2) = GrossSurfaceArea (m2) = NetSurfaceArea (m2) | NetSurfaceAreaExtrudedSides (m2) = OuterSurfaceArea (m2) | Concreto - Estrutural, Massa (kg)
V01 | V01 | Sala de estar | 06 | 82.1177 (kgCO₂) | 796.293 | 1.288 | 6440 | 0.9016 | 0.18032 | 4.4352 | 4.3792 | 414.736 | ArchiCADProperties - Zonas em Colisão: Sala de estar
V02 | V02 | Dormitório 3 | 02 | 40.1663 (kgCO₂) | 389.491 | 0.63 | 3150 | 0.441 | 0.0882 | 2.198 | 2.142 | 202.86
V04 | V04 | Sala de estar | 06 | 38.3811 (kgCO₂) | 372.18 | 0.602 | 3010 | 0.4214 | 0.08428 | 2.1028 | 2.0468 | 193.844
V03 | V03 | Dormitório 3 | 02 | 80.3326 (kgCO₂) | 778.982 | 1.26 | 6300 | 0.882 | 0.1764 | 4.34 | 4.284 | 405.72

# IfcBeam: Madeiramento - Cobertura 100 x 160 (4)
In: Cobertura
Description: Terça-externa-inloco-madeira-16cm x 10cm; Classification: 3E 12 06 02 00 Viga (NBR 15965-5 3E); Terça de Telhado (Classificação Archicad); Material: Madeiramento - Cobertura
Pset_ManufacturerTypeInformation - ProductionYear: DD/MM/YYYY
ArchiCADProperties - Corte Transversal da Viga: Retangular; Superfície Extremidade: Madeira - Pinho Granulado Horizontal; Superfície Lado Esquerdo: Madeira - Pinho Granulado Horizontal; Superfície Lado Direito: Madeira - Pinho Granulado Horizontal; Ângulo de Inclinação da Viga: 0 deg; Geração Modelo Analítico Estrutural: yes; Membro Alongado Manualmente: no; Vegetal: EST - Viga; Material de Construção/ Composição / Perfil / Trama: Madeiramento - Cobertura; Material de Construção: Madeiramento - Cobertura; Protegido: no; Nome Piso de Origem: Cobertura; Número Piso de Origem: 1; Tipo de Elemento: Viga; Tipo: Básica; Materiais de Construção (Todos): Madeiramento - Cobertura; Superfícies (Todas): Madeira - Pinho Granulado Horizontal; Trama em Vista: Trama Vazia; Ângulo de Inclinação: 0 deg; Número de Aberturas: 0; Superfície do Topo: Madeira - Pinho Granulado Horizontal; Superfície da Base: Madeira - Pinho Granulado Horizontal; Nome das Opções de Projeto: Modelo Principal; Nome do Conjunto de Opções de Projeto: Modelo Principal; Posição: Exterior; Mostrar em Filtro de Renovação: Todos os Filtros Relevantes; Função Estrutural: Elemento Estrutural; Estado de Renovação: Existente; Estado das Opções de Projeto: Modelo Principal; Conjunto de Opções de Projeto: Modelo Principal
Pset_BeamCommon - IsExternal: yes; LoadBearing: yes; Reference: Madeiramento - Cobertura 100 x 160
Component Properties - Madeiramento - Cobertura, Carbono Incorporado: 24.48 (kgCO₂); Madeiramento - Cobertura, Energia Incorporada: 680 MJ; Madeiramento - Cobertura, Tipo de Componente: Núcleo
Material Properties - Madeiramento - Cobertura, ThermalConductivity: 0.14; Madeiramento - Cobertura, SpecificHeatCapacity: 2300 J/kg/K; Madeiramento - Cobertura, MassDensity: 500 kg/m3; Madeiramento - Cobertura, Embodied Energy: 10 (MJ/kg); Madeiramento - Cobertura, Embodied Carbon: 0.36 (kgCO₂/kg); Madeiramento - Cobertura, Name: Madeiramento - Cobertura; Madeiramento - Cobertura, ID: MAD; Madeiramento - Cobertura, Participates in Collision Detection: yes
ArchiCADQuantities - Área da Superfície das Extremidades da Viga: 0.032 m2; Número Furo: 0; Área da Borda do Furo: 0 m2; Área de Superfície dos Furos: 0 m2; Volume Furos: 0 m3; Área da Superfície do Lado Esquerdo da Viga (Líquida): 1.36 m2; Comprimento Esquerda: 8500 mm; Comprimento Direita: 8500 mm; Afastamento Eixo a partir do Centro: 0 mm; Área da Superfície do Lado Direito da Viga (Líquida): 1.36 m2; Área: 0.85 m2; Altura: 160 mm; Volume (Líquido): 0.136 m3; Largura: 100 mm; Área da Superfície: 4.452 m2; Comprimento 3D: 8500 mm; Volume (Condicional): 0.136 m3; Volume (Bruto): 0.136 m3; Altura do Corte Transversal no Topo/Terminação (perpendicular): 160 mm; Altura do Corte Transversal na Base/Início (perpendicular): 160 mm; Largura do Corte Transversal no Topo/Terminação (perpendicular): 100 mm; Largura do Corte Transversal na Base/Início (perpendicular): 100 mm; Altura do Corte Transversal no Topo/Terminação (corte): 160 mm; Altura do Corte Transversal na Base/Início (corte): 160 mm; Largura do Corte Transversal no Topo/Terminação (corte): 100 mm; Largura do Corte Transversal na Base/Início (corte): 100 mm; Área do Corte Transversal na Base/Início: 0.016 m2; Altura do Corte Transversal no Topo/Terminação: 0.016 m2; Número de Segmentos: 1; Área da Superfície do Topo (Líquida): 0.85 m2; Área da Superfície da Base (Líquida): 0.85 m2
BaseQuantities - NetSurfaceAreaExtrudedSides: 4.42 m2; Length: 8500 mm; Width: 100 mm; Depth: 160 mm; CrossSectionArea: 0.016 m2; OuterSurfaceArea: 4.42 m2; TotalSurfaceArea: 4.452 m2; GrossSurfaceArea: 4.452 m2; GrossVolume: 0.136 m3; NetSurfaceArea: 4.452 m2; NetVolume: 0.136 m3
Component Quantities - Madeiramento - Cobertura, Massa: 68 kg; Madeiramento - Cobertura, Área de Componente Projetada (Líquida): 1.36 m2; Madeiramento - Cobertura, Área de Componente Projetada (Bruta): 1.36 m2; Madeiramento - Cobertura, Espessura do Componente: 100 mm; Madeiramento - Cobertura, Altura do Componente Retangular: 160 mm; Madeiramento - Cobertura, Largura do Componente Retangular: 100 mm; Madeiramento - Cobertura, Área de Seção Transversal do Componente: 0.016 m2; Madeiramento - Cobertura, Volume Componente (Líquido): 0.136 m3; Madeiramento - Cobertura, Volume do componente (Bruto): 0.136 m3
AC_Pset_RenovationAndPhasing - Renovation Status: Existing
Name | ID do Elemento = ID do Elemento e Associação = ID Pai | Elevação à Origem do Projeto (mm) = Elevação ao 1º Nível de Referência (mm) = Elevação ao 2º Nível de Referência (mm) = Elevação ao Nível do Mar (mm) = Elevação do Topo ao Primeiro Nível de Referência (mm) = Elevação do Topo À Cota Zero (mm) = Elevação do Topo Ao Nível do Mar (mm) = Elevação do Topo Ao Segundo Nível de Referência (mm) | Elevação ao Piso (mm) = Afastamento do Piso de Origem (mm) = Elevação do Topo Ao Piso de Origem (mm) | Elevação da Base Ao Primeiro Nível de Referência (mm) = Elevação da Base À Cota Zero (mm) = Elevação da Base Ao Nível do Mar (mm) = Elevação da Base Ao Segundo Nível de Referência (mm) | Elevação da Base Ao Piso de Origem (mm)
T01 | T01 | 2660 | 160 | 2500 | 0
T03 | T03 | 3582.95 | 1082.95 | 3422.95 | 922.952
T04 | T04 | 3140.45 | 640.452 | 2980.45 | 480.452
T02 | T02 | 3140.45 | 640.452 | 2980.45 | 480.452

# IfcBeam: Madeiramento - Cobertura 100 x 80, T05
In: Cobertura
Description: Terça-externa-inloco-madeira-16cm x 10cm; Classification: 3E 12 06 02 00 Viga (NBR 15965-5 3E); Terça de Telhado (Classificação Archicad); Material: Madeiramento - Cobertura
Pset_ManufacturerTypeInformation - ProductionYear: DD/MM/YYYY
ArchiCADQuantities - Área da Superfície das Extremidades da Viga: 0.016 m2; Número Furo: 0; Área da Borda do Furo: 0 m2; Área de Superfície dos Furos: 0 m2; Volume Furos: 0 m3; Área da Superfície do Lado Esquerdo da Viga (Líquida): 0.68 m2; Comprimento Esquerda: 8500 mm; Comprimento Direita: 8500 mm; Afastamento Eixo a partir do Centro: 0 mm; Área da Superfície do Lado Direito da Viga (Líquida): 0.68 m2; Área: 0.85 m2; Altura: 80 mm; Volume (Líquido): 0.068 m3; Largura: 100 mm; Elevação à Origem do Projeto: 2660 mm; Elevação ao 1º Nível de Referência: 2660 mm; Elevação ao 2º Nível de Referência: 2660 mm; Elevação ao Nível do Mar: 2660 mm; Elevação ao Piso: 160 mm; Afastamento do Piso de Origem: 160 mm; Área da Superfície: 3.076 m2; Comprimento 3D: 8500 mm; Volume (Condicional): 0.068 m3; Volume (Bruto): 0.068 m3; Elevação do Topo ao Primeiro Nível de Referência: 2660 mm; Elevação do Topo Ao Piso de Origem: 160 mm; Elevação do Topo À Cota Zero: 2660 mm; Elevação do Topo Ao Nível do Mar: 2660 mm; Elevação do Topo Ao Segundo Nível de Referência: 2660 mm; Elevação da Base Ao Primeiro Nível de Referência: 2580 mm; Elevação da Base Ao Piso de Origem: 80 mm; Elevação da Base À Cota Zero: 2580 mm; Elevação da Base Ao Nível do Mar: 2580 mm; Elevação da Base Ao Segundo Nível de Referência: 2580 mm; Altura do Corte Transversal no Topo/Terminação (perpendicular): 80 mm; Altura do Corte Transversal na Base/Início (perpendicular): 80 mm; Largura do Corte Transversal no Topo/Terminação (perpendicular): 100 mm; Largura do Corte Transversal na Base/Início (perpendicular): 100 mm; Altura do Corte Transversal no Topo/Terminação (corte): 80 mm; Altura do Corte Transversal na Base/Início (corte): 80 mm; Largura do Corte Transversal no Topo/Terminação (corte): 100 mm; Largura do Corte Transversal na Base/Início (corte): 100 mm; Área do Corte Transversal na Base/Início: 0.008 m2; Altura do Corte Transversal no Topo/Terminação: 0.008 m2; Número de Segmentos: 1; Área da Superfície do Topo (Líquida): 0.85 m2; Área da Superfície da Base (Líquida): 0.85 m2
Component Quantities - Madeiramento - Cobertura, Massa: 34 kg; Madeiramento - Cobertura, Área de Componente Projetada (Líquida): 0.68 m2; Madeiramento - Cobertura, Área de Componente Projetada (Bruta): 0.68 m2; Madeiramento - Cobertura, Espessura do Componente: 100 mm; Madeiramento - Cobertura, Altura do Componente Retangular: 80 mm; Madeiramento - Cobertura, Largura do Componente Retangular: 100 mm; Madeiramento - Cobertura, Área de Seção Transversal do Componente: 0.008 m2; Madeiramento - Cobertura, Volume Componente (Líquido): 0.068 m3; Madeiramento - Cobertura, Volume do componente (Bruto): 0.068 m3
Material Properties - Madeiramento - Cobertura, ThermalConductivity: 0.14; Madeiramento - Cobertura, SpecificHeatCapacity: 2300 J/kg/K; Madeiramento - Cobertura, MassDensity: 500 kg/m3; Madeiramento - Cobertura, Embodied Energy: 10 (MJ/kg); Madeiramento - Cobertura, Embodied Carbon: 0.36 (kgCO₂/kg); Madeiramento - Cobertura, Name: Madeiramento - Cobertura; Madeiramento - Cobertura, ID: MAD; Madeiramento - Cobertura, Participates in Collision Detection: yes
BaseQuantities - NetSurfaceAreaExtrudedSides: 3.06 m2; Length: 8500 mm; Width: 100 mm; Depth: 80 mm; CrossSectionArea: 0.008 m2; OuterSurfaceArea: 3.06 m2; TotalSurfaceArea: 3.076 m2; GrossSurfaceArea: 3.076 m2; GrossVolume: 0.068 m3; NetSurfaceArea: 3.076 m2; NetVolume: 0.068 m3
Pset_BeamCommon - IsExternal: yes; LoadBearing: yes; Reference: Madeiramento - Cobertura 100 x 80
Component Properties - Madeiramento - Cobertura, Carbono Incorporado: 12.24 (kgCO₂); Madeiramento - Cobertura, Energia Incorporada: 340 MJ; Madeiramento - Cobertura, Tipo de Componente: Núcleo
ArchiCADProperties - Corte Transversal da Viga: Retangular; Superfície Extremidade: Madeira - Pinho Granulado Horizontal; Superfície Lado Esquerdo: Madeira - Pinho Granulado Horizontal; Superfície Lado Direito: Madeira - Pinho Granulado Horizontal; Ângulo de Inclinação da Viga: 0 deg; Geração Modelo Analítico Estrutural: yes; Membro Alongado Manualmente: no; ID do Elemento: T05; ID do Elemento e Associação: T05; Vegetal: EST - Viga; Material de Construção/ Composição / Perfil / Trama: Madeiramento - Cobertura; Material de Construção: Madeiramento - Cobertura; Protegido: no; Nome Piso de Origem: Cobertura; Número Piso de Origem: 1; Tipo de Elemento: Viga; Tipo: Básica; ID Pai: T05; Materiais de Construção (Todos): Madeiramento - Cobertura; Superfícies (Todas): Madeira - Pinho Granulado Horizontal; Trama em Vista: Trama Vazia; Ângulo de Inclinação: 0 deg; Número de Aberturas: 0; Superfície do Topo: Madeira - Pinho Granulado Horizontal; Superfície da Base: Madeira - Pinho Granulado Horizontal; Nome das Opções de Projeto: Modelo Principal; Nome do Conjunto de Opções de Projeto: Modelo Principal; Posição: Exterior; Mostrar em Filtro de Renovação: Todos os Filtros Relevantes; Função Estrutural: Elemento Estrutural; Estado de Renovação: Existente; Estado das Opções de Projeto: Modelo Principal; Conjunto de Opções de Projeto: Modelo Principal
AC_Pset_RenovationAndPhasing - Renovation Status: Existing

# IfcBuildingElementPart (17)
Material: Bloco de Concreto - Estrutural DEF
Material Properties - Bloco de Concreto - Estrutural DEF, ThermalConductivity: 0.6; Bloco de Concreto - Estrutural DEF, SpecificHeatCapacity: 880 J/kg/K; Bloco de Concreto - Estrutural DEF, MassDensity: 1400 kg/m3; Bloco de Concreto - Estrutural DEF, Embodied Energy: 0.72 (MJ/kg); Bloco de Concreto - Estrutural DEF, Embodied Carbon: 0.088 (kgCO₂/kg); Bloco de Concreto - Estrutural DEF, Name: Bloco de Concreto - Estrutural DEF; Bloco de Concreto - Estrutural DEF, ID: BLO CON EST; Bloco de Concreto - Estrutural DEF, Description: Bloco_concreto-interno-inloco-14cm; Bloco de Concreto - Estrutural DEF, Participates in Collision Detection: yes
Component Quantities - Espessura do Componente: 140 mm; Largura do Componente Retangular: 140 mm
Name | In | Carbono Incorporado | Energia Incorporada (MJ) | Tipo de Componente | Massa (kg) | Área de Componente Projetada (Líquida) (m2) | Área de Componente Projetada (Bruta) (m2) | Área de Componente Projetada (Condicional) (m2) | Altura do Componente Retangular (mm) | Área de Seção Transversal do Componente (m2) | Volume Componente (Líquido) (m3) | Volume do componente (Bruto) (m3) = Volume Componente (Condicional) (m3)
Bloco de Concreto - Estrutural DEF | Pavimento Térreo | 225.164 (kgCO₂) | 1842.25 | Núcleo | 2558.68 | 13.0545 | 15.4545 | 15.4545 | 2500 | 0.35 | 1.82763 | 2.16363
Bloco de Concreto - Estrutural DEF | Pavimento Térreo | 318.657 (kgCO₂) | 2607.19 | Núcleo | 3621.1 | 18.475 | 20.875 | 20.875 | 2500 | 0.35 | 2.5865 | 2.9225
Bloco de Concreto - Estrutural DEF | Pavimento Térreo | 135.147 (kgCO₂) | 1105.75 | Núcleo | 1535.76 | 7.8625 | 7.8625 | 7.8625 | 2500 | 0.35 | 1.09697 | 1.09697
Bloco de Concreto - Estrutural DEF | Pavimento Térreo | 98.8335 (kgCO₂) | 808.638 | Acabamento | 1123.11 | 5.761 | 7.601 | 7.601 | 2500 | 0.35 | 0.80222 | 1.06414
Bloco de Concreto - Estrutural DEF | Pavimento Térreo | 160.997 (kgCO₂) | 1317.25 | Núcleo | 1829.52 | 9.33426 | 17.7065 | 9.33426 | 5897.79 | 0.82569 | 1.3068 | 2.4789
Bloco de Concreto - Estrutural DEF | Pavimento Térreo | 86.24 (kgCO₂) | 705.6 | Acabamento | 980 | 5 | 5 | 5 | 2500 | 0.35 | 0.7 | 0.7
Bloco de Concreto - Estrutural DEF | Pavimento Térreo | 6.468 (kgCO₂) | 52.92 | Acabamento | 73.5 | 0.375 | 0.375 | 0.375 | 2500 | 0.35 | 0.0525 | 0.0525
Bloco de Concreto - Estrutural DEF | Pavimento Térreo | 245.836 (kgCO₂) | 2011.38 | Núcleo | 2793.59 | 14.253 | 19.293 | 19.293 | 2500 | 0.35 | 1.99542 | 2.70102
Bloco de Concreto - Estrutural DEF | Pavimento Térreo | 91.4403 (kgCO₂) | 748.148 | Núcleo | 1039.09 | 5.3015 | 5.3015 | 5.3015 | 2500 | 0.35 | 0.74221 | 0.74221
Bloco de Concreto - Estrutural DEF | Pavimento Térreo | 74.1664 (kgCO₂) | 606.816 | Núcleo | 842.8 | 4.3 | 5.98 | 5.98 | 2500 | 0.35 | 0.602 | 0.8372
Bloco de Concreto - Estrutural DEF | Pavimento Térreo | 85.6406 (kgCO₂) | 700.696 | Acabamento | 973.189 | 5.35 | 5.35 | 5.35 | 2500 | 0.35 | 0.695135 | 0.695135
Bloco de Concreto - Estrutural DEF | Pavimento Térreo | 5.95056 (kgCO₂) | 48.6864 | Núcleo | 67.62 | 0.345 | 0.345 | 0.345 | 2500 | 0.35 | 0.0483 | 0.0483
Bloco de Concreto - Estrutural DEF | Pavimento Térreo | 40.3905 (kgCO₂) | 330.468 | Núcleo | 458.983 | 2.5375 | 2.5375 | 2.5375 | 2500 | 0.35 | 0.327845 | 0.327845
Bloco de Concreto - Estrutural DEF | Pavimento Térreo | 18.671 (kgCO₂) | 152.762 | Acabamento | 212.17 | 1.0825 | 2.7625 | 2.7625 | 2500 | 0.35 | 0.15155 | 0.38675
Bloco de Concreto - Estrutural DEF | Cobertura | 60.8705 (kgCO₂) | 498.031 | Núcleo | 691.71 | 3.52913 | 6.96169 | 3.52913 | 1176.31 | 0.164683 | 0.494079 | 0.974637
Bloco de Concreto - Estrutural DEF | Cobertura | 60.9381 (kgCO₂) | 498.584 | Núcleo | 692.478 | 3.53305 | 6.9911 | 3.53305 | 1176.31 | 0.164683 | 0.494627 | 0.978754
Bloco de Concreto - Estrutural DEF | Cobertura | 119.367 (kgCO₂) | 976.64 | Núcleo | 1356.44 | 6.92063 | 6.92063 | 6.92063 | 922.952 | 0.129213 | 0.968889 | 0.968889

# IfcColumn: Madeiramento - Cobertura 150 x 100 (4)
In: Cobertura
Description: Pontalete-interno-inloco-madeira-10x15cm; Classification: Pontalete de Telhado (Classificação Archicad); 3E 14 04 02 14 Pontalete (NBR 15965-5 3E); Material: Madeiramento - Cobertura
Pset_ManufacturerTypeInformation - ProductionYear: DD/MM/YYYY
ArchiCADProperties - Corte Transversal do Pilar: Retangular; Ângulo de Inclinação do Pilar: 90 deg; Superfície de Extrusão: Madeira - Pinho Granulado Horizontal; Superfície Terminação: Madeira - Pinho Granulado Horizontal; Geração Modelo Analítico Estrutural: yes; Membro Alongado Manualmente: no; Vegetal: EST - Pilar; Material de Construção/ Composição / Perfil / Trama: Madeiramento - Cobertura; Material de Construção: Madeiramento - Cobertura; Protegido: no; Nome Piso de Origem: Cobertura; Número Piso de Origem: 1; Tipo de Elemento: Pilar; Ponto de Vínculo do Piso Absoluto: Não Vinculado; Ponto de Vínculo do Piso Relativo: Não Vinculado; Vínculo Superior do Piso: Não Vinculado; Tipo: Básica; Materiais de Construção (Todos): Madeiramento - Cobertura; Superfícies (Todas): Madeira - Pinho Granulado Horizontal; Trama em Vista: Trama Vazia; Ângulo de Inclinação: 90 deg; Nome das Opções de Projeto: Modelo Principal; Nome do Conjunto de Opções de Projeto: Modelo Principal; Posição: Interior; Mostrar em Filtro de Renovação: Todos os Filtros Relevantes; Função Estrutural: Elemento Estrutural; Estado de Renovação: Existente; Estado das Opções de Projeto: Modelo Principal; Conjunto de Opções de Projeto: Modelo Principal
AC_Pset_RenovationAndPhasing - Renovation Status: Existing
Component Properties - Madeiramento - Cobertura, Carbono Incorporado: 0.945 (kgCO₂); Madeiramento - Cobertura, Energia Incorporada: 26.25 MJ; Madeiramento - Cobertura, Tipo de Componente: Núcleo
Pset_ColumnCommon - IsExternal: no; LoadBearing: yes; Reference: Madeiramento - Cobertura 150 x 100
ArchiCADQuantities - Diâmetro / Altura do Núcleo: 100 mm; Volume do Núcleo do Pilar (Líquido): 0.00525 m3; Largura Núcleo: 150 mm; Área da Superfície do Núcleo do Pilar (Bruta, sem Topo/Base): 0.175 m2; Área da Superfície do Topo do Núcleo do Pilar (Bruta): 0.015 m2; Área da Superfície da Base do Núcleo do Pilar (Bruta): 0.015 m2; Volume do Núcleo do Pilar (Bruto): 0.00525 m3; Área de Superfície do Revestimento do Pilar (Bruta, sem Topo/Base): 0 m2; Área da Superfície do Topo do Revestimento do Pilar (Bruta): 0 m2; Área da Superfíciena da Base do Revestimento do Pilar (Bruta): 0 m2; Volume do Revestimento do Pilar (Bruto): 0 m3; Altura máxima do pilar: 350 mm; Altura mínima do pilar: 350 mm; Área da Superfície da Base do Núcleo do Pilar (Líquida): 0.015 m2; Área da Superfície do Núcleo do Pilar (Líquida, sem Topo/Base): 0.175 m2; Área da Superfície do Topo do Núcleo do Pilar (Líquida): 0.015 m2; Área da Superfície da Base do Revestimento do Pilar (Líquida): 0 m2; Área da Superfície do Revestimento do Pilar (Líquida): 0 m2; Área da Superfície do Topo do Revestimento do Pilar (Líquida): 0 m2; Perímetro do Perfil da Coluna (base): 500 mm; Volume do Revestimento do Pilar (Líquido): 0 m3; Área: 0.015 m2; Altura: 350 mm; Volume (Líquido): 0.00525 m3; Largura: 150 mm; Elevação à Origem do Projeto: 2630 mm; Elevação ao 1º Nível de Referência: 2630 mm; Elevação ao 2º Nível de Referência: 2630 mm; Elevação ao Nível do Mar: 2630 mm; Elevação ao Piso: 130 mm; Afastamento do Piso de Origem: 130 mm; Afastamento do Topo: -280 mm; Área da Superfície: 0.175 m2; Comprimento 3D: 350 mm; Volume (Bruto): 0.00525 m3; Elevação do Topo ao Primeiro Nível de Referência: 2980 mm; Elevação do Topo Ao Piso de Origem: 480 mm; Elevação do Topo À Cota Zero: 2980 mm; Elevação do Topo Ao Nível do Mar: 2980 mm; Elevação do Topo Ao Segundo Nível de Referência: 2980 mm; Elevação da Base Ao Primeiro Nível de Referência: 2630 mm; Elevação da Base Ao Piso de Origem: 130 mm; Elevação da Base À Cota Zero: 2630 mm; Elevação da Base Ao Nível do Mar: 2630 mm; Elevação da Base Ao Segundo Nível de Referência: 2630 mm; Altura do Corte Transversal no Topo/Terminação (perpendicular): 100 mm; Altura do Corte Transversal na Base/Início (perpendicular): 100 mm; Largura do Corte Transversal no Topo/Terminação (perpendicular): 150 mm; Largura do Corte Transversal na Base/Início (perpendicular): 150 mm; Altura do Corte Transversal no Topo/Terminação (corte): 100 mm; Altura do Corte Transversal na Base/Início (corte): 100 mm; Largura do Corte Transversal no Topo/Terminação (corte): 150 mm; Largura do Corte Transversal na Base/Início (corte): 150 mm; Área do Corte Transversal na Base/Início: 0.015 m2; Altura do Corte Transversal no Topo/Terminação: 0.015 m2; Número de Segmentos: 1; Área da Superfície do Topo (Líquida): 0.015 m2; Área da Superfície da Base (Líquida): 0.175 m2; Área da Superfície do Topo (Bruta): 0.015 m2
BaseQuantities - Length: 350 mm; Width: 150 mm; Depth: 100 mm; CrossSectionArea: 0.015 m2; OuterSurfaceArea: 0.175 m2; TotalSurfaceArea: 0.205 m2; GrossSurfaceArea: 0.205 m2; GrossVolume: 0.00525 m3; NetVolume: 0.00525 m3
Component Quantities - Madeiramento - Cobertura, Massa: 2.625 kg; Madeiramento - Cobertura, Espessura do Componente: 150 mm; Madeiramento - Cobertura, Altura do Componente Retangular: 100 mm; Madeiramento - Cobertura, Largura do Componente Retangular: 150 mm; Madeiramento - Cobertura, Área de Seção Transversal do Componente: 0.015 m2; Madeiramento - Cobertura, Volume Componente (Líquido): 0.00525 m3; Madeiramento - Cobertura, Volume do componente (Bruto): 0.00525 m3
Material Properties - Madeiramento - Cobertura, ThermalConductivity: 0.14; Madeiramento - Cobertura, SpecificHeatCapacity: 2300 J/kg/K; Madeiramento - Cobertura, MassDensity: 500 kg/m3; Madeiramento - Cobertura, Embodied Energy: 10 (MJ/kg); Madeiramento - Cobertura, Embodied Carbon: 0.36 (kgCO₂/kg); Madeiramento - Cobertura, Name: Madeiramento - Cobertura; Madeiramento - Cobertura, ID: MAD; Madeiramento - Cobertura, Participates in Collision Detection: yes
Name | ID do Elemento = ID do Elemento e Associação = ID Pai
PIL03 | PIL03
PIL02 | PIL02
PIL04 | PIL04
PIL01 | PIL01

# IfcCovering (40)
PredefinedType: CLADDING
Pset_CoveringCommon - AcousticRating: 0,00
Pset_ManufacturerTypeInformation - ProductionYear: DD/MM/YYYY
Name | In | Material | Carbono Incorporado | Energia Incorporada (MJ) | Tipo de Componente | Reboco DEF, ThermalConductivity | Reboco DEF, SpecificHeatCapacity (J/kg/K) | Reboco DEF, MassDensity (kg/m3) | Reboco DEF, Embodied Energy | Reboco DEF, Embodied Carbon | Reboco DEF, Name | Reboco DEF, ID | Reboco DEF, Description | Reboco DEF, Participates in Collision Detection | Reboco DEF, Data de Aquisição = Reboco DEF, Data de Fabricação | Reboco DEF, Site do Produto | Reboco DEF, Índice de Perda (%) | Massa (kg) | Área de Componente Projetada (Líquida) (m2) | Área de Componente Projetada (Bruta) (m2) | Espessura do Componente (mm) = Largura do Componente Retangular (mm) | Altura do Componente Retangular (mm) | Área de Seção Transversal do Componente (m2) | Volume Componente (Líquido) (m3) | Volume do componente (Bruto) (m3)
Reboco DEF | Pavimento Térreo | Reboco DEF | 11.5976 (kgCO₂) | 160.582 | Acabamento | 0.57 | 1000 | 1300 | 1.8 (MJ/kg) | 0.13 (kgCO₂/kg) | Reboco DEF | REB | Reboco-interno-inloco-5mm | yes | DD/MM/YYYY | www.graphisoft.com | 10 | 89.2125 | 13.725 | 16.125 | 5 | 2500 | 0.0125 | 0.068625 | 0.080625
Reboco DEF | Pavimento Térreo | Reboco DEF | 10.9956 (kgCO₂) | 152.246 | Acabamento | 0.57 | 1000 | 1300 | 1.8 (MJ/kg) | 0.13 (kgCO₂/kg) | Reboco DEF | REB | Reboco-interno-inloco-5mm | yes | DD/MM/YYYY | www.graphisoft.com | 10 | 84.5813 | 13.0125 | 15.4125 | 5 | 2500 | 0.0125 | 0.0650625 | 0.0770625
2 x Reboco DEF | Pavimento Térreo | Reboco DEF | 15.6114 (kgCO₂) | 216.158 | Acabamento | 0.57 | 1000 | 1300 | 1.8 (MJ/kg) | 0.13 (kgCO₂/kg) | Reboco DEF | REB | Reboco-interno-inloco-5mm | yes | DD/MM/YYYY | www.graphisoft.com | 10 | 120.088 | 18.475 | 20.875 | 5 | 2500 | 0.0125 | 0.092375 | 0.104375
Reboco DEF | Pavimento Térreo | Reboco DEF | 6.62015 (kgCO₂) | 91.6637 | Acabamento | 0.57 | 1000 | 1300 | 1.8 (MJ/kg) | 0.13 (kgCO₂/kg) | Reboco DEF | REB | Reboco-interno-inloco-5mm | yes | DD/MM/YYYY | www.graphisoft.com | 10 | 50.9243 | 7.8345 | 7.8345 | 5 | 2500 | 0.0125 | 0.0391725 | 0.0391725
Reboco DEF | Pavimento Térreo | Reboco DEF | 6.64381 (kgCO₂) | 91.9913 | Acabamento | 0.57 | 1000 | 1300 | 1.8 (MJ/kg) | 0.13 (kgCO₂/kg) | Reboco DEF | REB | Reboco-interno-inloco-5mm | yes | DD/MM/YYYY | www.graphisoft.com | 10 | 51.1063 | 7.8625 | 7.8625 | 5 | 2500 | 0.0125 | 0.0393125 | 0.0393125
Reboco DEF | Pavimento Térreo | Reboco DEF | 5.03282 (kgCO₂) | 69.6852 | Acabamento | 0.57 | 1000 | 1300 | 1.8 (MJ/kg) | 0.13 (kgCO₂/kg) | Reboco DEF | REB | Reboco-interno-inloco-5mm | yes | DD/MM/YYYY | www.graphisoft.com | 10 | 38.714 | 5.956 | 7.85 | 5 | 2500 | 0.0125 | 0.02978 | 0.03925
Argamassa Colante DEF | Pavimento Térreo | Argamassa Colante DEF | 23.0423 (kgCO₂) | 144.961 | Núcleo |  |  |  |  |  |  |  |  |  |  |  |  | 108.18 | 6.01 | 7.85 | 10 | 2500 | 0.025 | 0.0601 | 0.0785 | Material Properties - Argamassa Colante DEF, ThermalConductivity: 1; Argamassa Colante DEF, SpecificHeatCapacity: 1000 J/kg/K; Argamassa Colante DEF, MassDensity: 1800 kg/m3; Argamassa Colante DEF, Embodied Energy: 1.34 (MJ/kg); Argamassa Colante DEF, Embodied Carbon: 0.213 (kgCO₂/kg); Argamassa Colante DEF, Name: Argamassa Colante DEF; Argamassa Colante DEF, ID: ARG COL; Argamassa Colante DEF, Description: Argamassa_colante-interna-inloco-5mm; Argamassa Colante DEF, Participates in Collision Detection: yes; Argamassa Colante DEF, Data de Aquisição: DD/MM/YYYY; Argamassa Colante DEF, Data de Fabricação: DD/MM/YYYY; Argamassa Colante DEF, Site do Produto: www.graphisoft.com; Argamassa Colante DEF, Índice de Perda (%): 10
Azulejo DEF | Pavimento Térreo | Azulejo DEF | 10.818 (kgCO₂) | 135.225 | Acabamento |  |  |  |  |  |  |  |  |  |  |  |  | 45.075 | 6.01 | 7.85 | 5 | 2500 | 0.0125 | 0.03005 | 0.03925 | Material Properties - Azulejo DEF, ThermalConductivity: 0.6; Azulejo DEF, SpecificHeatCapacity: 840 J/kg/K; Azulejo DEF, MassDensity: 1500 kg/m3; Azulejo DEF, Embodied Energy: 3 (MJ/kg); Azulejo DEF, Embodied Carbon: 0.24 (kgCO₂/kg); Azulejo DEF, Name: Azulejo DEF; Azulejo DEF, ID: AZU; Azulejo DEF, Description: Azulejo-interno-inloco-cerâmico-1cm; Azulejo DEF, Participates in Collision Detection: yes; Azulejo DEF, Data de Aquisição: DD/MM/YYYY; Azulejo DEF, Data de Fabricação: DD/MM/YYYY; Azulejo DEF, Site do Produto: www.graphisoft.com; Azulejo DEF, Índice de Perda (%): 10
Azulejo DEF | Pavimento Térreo | Azulejo DEF | 0.675 (kgCO₂) | 8.4375 | Acabamento |  |  |  |  |  |  |  |  |  |  |  |  | 2.8125 | 0.375 | 0.375 | 5 | 2500 | 0.0125 | 0.001875 | 0.001875 | Material Properties - Azulejo DEF, ThermalConductivity: 0.6; Azulejo DEF, SpecificHeatCapacity: 840 J/kg/K; Azulejo DEF, MassDensity: 1500 kg/m3; Azulejo DEF, Embodied Energy: 3 (MJ/kg); Azulejo DEF, Embodied Carbon: 0.24 (kgCO₂/kg); Azulejo DEF, Name: Azulejo DEF; Azulejo DEF, ID: AZU; Azulejo DEF, Description: Azulejo-interno-inloco-cerâmico-1cm; Azulejo DEF, Participates in Collision Detection: yes; Azulejo DEF, Data de Aquisição: DD/MM/YYYY; Azulejo DEF, Data de Fabricação: DD/MM/YYYY; Azulejo DEF, Site do Produto: www.graphisoft.com; Azulejo DEF, Índice de Perda (%): 10
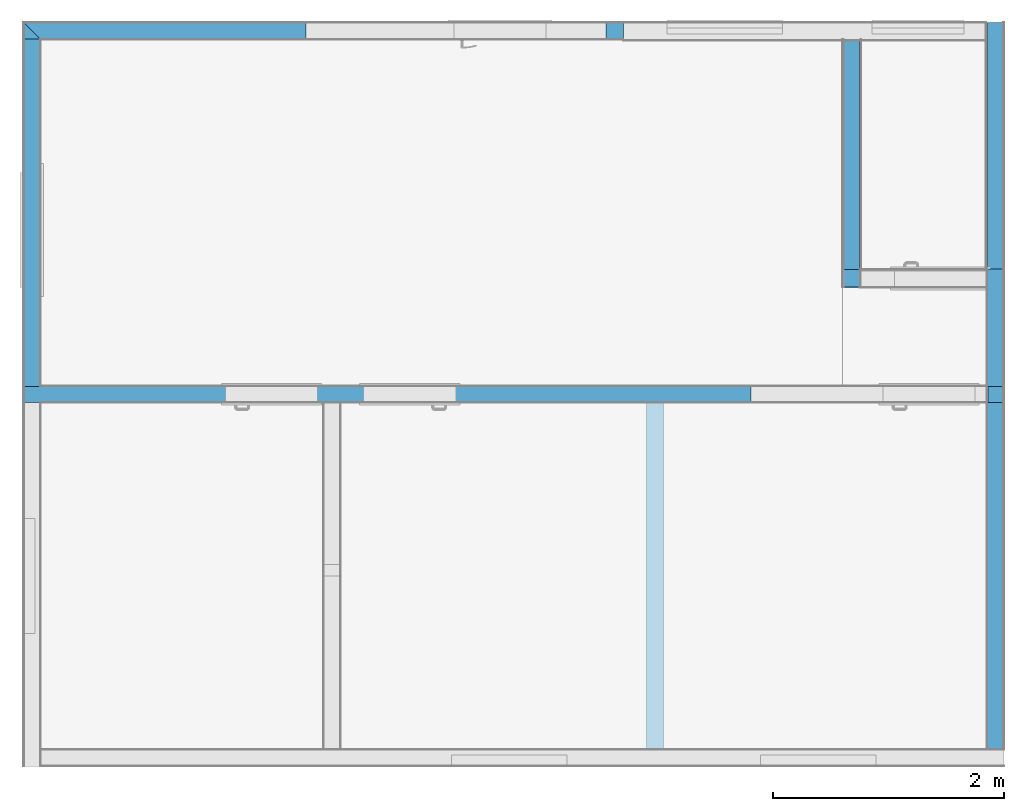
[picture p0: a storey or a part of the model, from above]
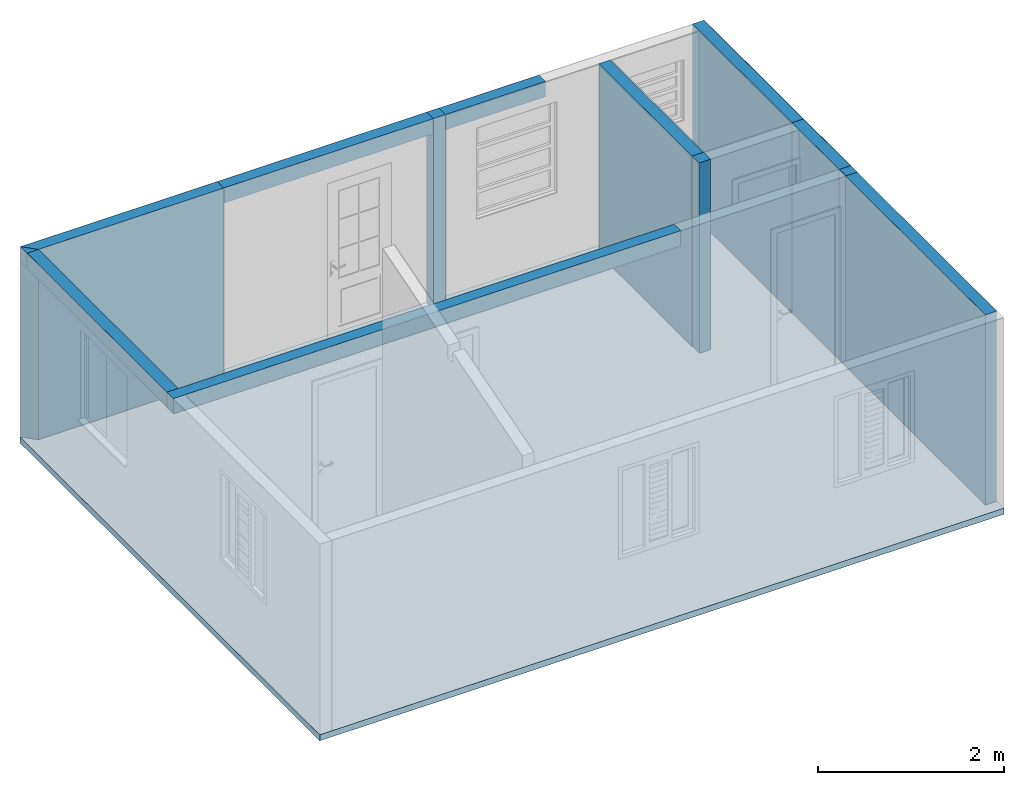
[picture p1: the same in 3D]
Properties of the parts of a building model (IFC2X3), part 4 of 6

# IfcDoor: Porta 27 (2)
AC_Pset_Porta_27 - Contornos Parede (0-Nenhum,1-Completo,2-Lado,3-Comprimento): 0; Pontos-Quentes 0-Nenhum,1-2D,2-3D,3-Todos: 3; Mostrar Pontos-Quentes 2D em 3D: yes; Opção de Visualização em Planta: 3; Ângulo de Posição da Abertura: 0 deg; Furo tem Superfície Lateral Parede: yes; Furos em Divisão de Superfícies são Curvos em Paredes Curvas: no; Tipo de Parede: 1; Tipo de Direção de Parede: 0; Posição de Ancoragem da Abertura: 1; Corda: no; Demolição / Nova Construção: 1; Novo Tipo de Trama de Parede: Bloco; Nova Caneta de Trama de Parede: Geral - Geral; Nova Caneta de Fundo de Trama de Parede: Fundos - Cor 1; Mostrar nova construção na Parede: no; Tipo de linha de demolição: 1; Mostrar parâmetro Demolição / Novo: no; Visualizar como Travessa: no; Luz Lateral (gs_SidelightTransomRelation): Abaixo da Bandeira; Luz Lateral (gs_SidelightTransomRelation_m): 1; Luz Lateral 1: no; Luz Lateral 2: no; Bandeira: no; Tolerâncias Uniformes: yes; Tamanho Nominal: 1; Definir Tamanho de Vão como Tamanho Nominal: yes; Definir Tamanho de Reentrância como Tamanho Nominal: no; Definir Tamanho de Unidade como Tamanho Nominal: no; Definir Tamanho de Saída como Tamanho Nominal: no; Definir Tamanho de Folha como Tamanho Nominal: no; Transferir Tamanho Nominal Atual para Seleção: no; Mostrar Pontos-Quentes Editáveis: yes; 2D: 1; Mostrar Face de Vão em Símbolo: 2; Indicação Simbólica da Abertura: no; 3D: 8; Direção Abertura Luz Lateral (gs_opening_dir_sl): Oposta à Folha; Direção Abertura Luz Lateral (gs_opening_dir_sl_m): 2; Batente Porta (gs_pocket_door_frame): yes; Estilo Batente (gs_frame_style): Rebaixo Samblado; Estilo Batente (gs_frame_style_m): 3; Espessura Batente=Espessura Parede: yes; Espessura Uniforme do Batente: yes; Folha Centrada: yes; Largura Uniforme Batente: yes; Estilo Batente Alterado Automaticamente: no; Número de Folhas da Porta: 4; Número de Folhas da Porta - Lado 2: 3; Estilo Painel Portas: 1; Configuração Folhas (gs_LeavesConfig): Folhas Uniformes; Configuração Folhas (gs_iLeavesConfig): 1; Posição Grelha (gs_grill_pos): Por tudo; Posição Grelha (gs_grill_pos_m): 3; Número de Paineis Verticais: 4; Número de Paineis Horizontais: 3; Nº Paineis Verticais Lado 1: 4; Nº Paineis Horizontais Lado 1: 3; Mostrar como Painel de Vidro em Símbolo: no; Mostrar Símbolo Porta Primav. Chinesa: no; Mostrar Símbolo como Painel Hermético: no; Maçaneta Abertura (gs_handle_type): Maçaneta 3; Maçaneta Abertura (gs_handle_type_m): 13; Mostrar Maçaneta em Símbolo: no; Proteção Borda Externa (bKickBoardOut): no; Proteção Borda Interna (bKickBoardIn): no; Caixilhos Uniformes: no; Tipo Abertura (gs_optype_m_05): 3; Tipo Abertura (gs_optype_m_09): 3; Tipo Abertura (gs_optype_m_02): 1; Tipo Abertura (gs_optype_m_06): 1; Tipo Abertura (gs_optype_m_10): 1; Tipo Caixilho (MullionStyle_00): Sem Grelha; Tipo Caixilho (iMullionStyle_00): 1; Tipo Caixilho (iMullionStyle_05): 1; Tipo Caixilho (iMullionStyle_09): 1; Tipo Caixilho (iMullionStyle_02): 1; Tipo Caixilho (iMullionStyle_06): 1; Tipo Caixilho (iMullionStyle_10): 1; Editar Ponto-quente Grelha: yes; Posição Grelha (MullionPosition): Por tudo; Posição Grelha (iMullionPosition): 3; Nº Paineis Verticais Caixilho Principal Lado 1: 4; Nº Paineis Horizontais Caixilho Principal Lado 1: 2; Nº Paineis Verticais 2 Caixilho Principal Lado 1: 4; Nº Paineis Horizontais 2 Caixilho Principal Lado 1: 2; Nº Paineis Verticais Caixilho Principal Lado 2: 4; Nº Paineis Horizontais Caixilho Principal Lado 2: 2; Nº Paineis Verticais 2 Caixilho Principal Lado 2: 4; Nº Paineis Horizontais 2 Caixilho Principal Lado 2: 2; Nº Paineis Verticais Bandeira Meio: 2; Nº Paineis Horizontais Bandeira Meio: 2; Nº Paineis Verticais 2 Bandeira Meio: 2; Nº Paineis Horizontais 2 Bandeira Meio: 2; Nº Paineis Verticais Bandeira Lado 1: 2; Nº Paineis Horizontais Bandeira Lado 1: 2; Nº Paineis Verticais 2 Bandeira Lado 1: 2; Nº Paineis Horizontais 2 Bandeira Lado 1: 2; Nº Paineis Verticais Bandeira Lado 2: 2; Nº Paineis Horizontais Bandeira Lado 2: 2; Nº Paineis Verticais 2 Bandeira Lado 2: 2; Nº Paineis Horizontais 2 Bandeira Lado 2: 2; Guarnição Externa: yes; Tipo Guarnição Externa (gs_trimtype_out): Simples; Tipo Guarnição Externa (gs_trimtype_out_int): 1; Tipo de Travessa Guarnição Externa: 1; Arquitrave Principal: yes; Tipo Arquitrave Principal: 1; Guarnição/Alizar na Superfície Externa da Parede: yes; Larguras Uniformes da Guarnição (gs_trim_outside_uniform): yes; Guarnição Interna: yes; Tipo Guarnição Interna (gs_trimtype_in): Simples; Tipo Guarnição Interna (gs_trimtype_in_int): 1; Guarnição/Alizar na Superfície Interna da Parede: yes; Larguras Uniformes da Guarnição (gs_trim_inside_uniform): yes; Soleira (bThreshold): no; Tipo de Soleira: 4; Ângulo Soleira: 3.1996 deg; Soleira Alterou Automaticamente: no; Soleira Externa - Porta: no; Peitoril - Luz Lateral Lado 1: no; Peitoril - Luz Lateral Lado 2: no; Sobredim. Peitoril: no; Tipo de Parapeito Exterior: 3; Ângulo Peitoril: 10 deg; Parapeito Curvo em Paredes Curvas: yes; Isolamento abaixo do Peitoril: yes; Usar Camada Isolamento de Parede: no; Nível Detalhe 3D Peitoril Tijolo: 1; Estilo de Peitoril Alterou Automaticamente: no; Peitoril Interno - Luz Lateral Lado 1: no; Peitoril Interno - Luz Lateral Lado 2: no; Peitoril Interno - Porta: no; Ângulo Peitoril Int.: 0 deg; Peitoril Int. Curvado em Paredes Curvas: yes; Peitoril Int. em Paredes Poligonais: 1; Ventilação Natural: no; Tipo Ventilação Natural: 2; Quebra-Sol: no; Tipo Quebra-Sol: 1; Tipos de Quebra-Sol Ativados: 126; Número de Paineis: 2; Número de Paineis 2: 1; Posição Painel (gs_shutter_panelPos): Simétrico; Posição Painel (gs_shutter_iPanelPos): 1; Altura Automática Veneziana: yes; Batente Extra: no; Tipo Cobertura (gs_slidingShutter_cover): Perfil-Z; Tipo Cobertura (gs_slidingShutter_iCover): 1; Direção de Empilham. (gs_foldingShutter_stacking): Dentro; Direção de Empilham. (gs_foldingShutter_iStacking): 1; Abrir em 3D: yes; Ângulo de abertura 3D: 180 deg; Mostrar Símbolo 2D: yes; Mostrar Linhas de Abertura no Símbolo: no; Tipo Painel (gs_shutPanel_type): Estilo 1; Tipo Painel (gs_shutPanel_iType): 1; Largura Base Batente Diferente: no; Largura Automática Veneziana: yes; Ângulo Grelha Ventilação: 30 deg; Nº Vãos Horiz.: 5; Nº Vãos Vert.: 8; Posição Rolamento Veneziana (gs_shutRoll_placement): Na Fachada; Posição Rolamento Veneziana (gs_shutRoll_iPlacement): 1; Tipo Caixa (gs_shutRoll_boxType): Rectangular; Tipo Caixa (gs_shutRoll_iBoxType): 1; Posição Grade (gs_shutRoll_railPos): Em Guarnição; Posição Grade (gs_shutRoll_iRailPos): 1; Mostrar Guarnição Atrás do Quebra-Sol (gs_shutRoll_showCasingBehind): no; Isolamento Atrás da Caixa (gs_shutRoll_cutWallBehind): no; Incluir Altura na Altura do Vão da Parede: no; Ângulo de Topo da Caixa: 10 deg; Largura Caixa Original (gs_shutRoll_boxDefaultSize): Largura Face de Vão; Largura Caixa Original (gs_shutRoll_iBoxDefaultSize): 1; Colocação Persianas (gs_shutLam_placement): Fixada na Fachada; Colocação Persianas (gs_shutLam_iPlacement): 1; Isolamento Atrás da Caixa (gs_shutLam_cutWallBehind): no; Caixa Aberta: yes; Trilho (gs_shutLam_bRail): yes; Posição Grade (gs_shutLam_railPos): Em Guarnição; Posição Grade (gs_shutLam_iRailPos): 1; Mostrar Guarnição Atrás do Quebra-Sol (gs_shutLam_showCasingBehind): no; Ângulo Rotação das Lamelas (gs_shutLam_rotation): 45 deg; Ângulo Rotação das Lamelas (gs_shutLam2_rotation): 45 deg; Arco de Alvenaria (bMasonryArch): no; Arco de Alvenaria (gs_masonry_arch_int): 2; Tipo de Arco de Alvenaria (gs_masonry_arch_structure): Arco de Reboco; Tipo de Arco de Alvenaria (gs_masonry_arch_structure_int): 1; Arco no Topo: yes; Nicho abaixo do Arco: yes; Ângulo de Plano do Arco: 75 deg; Superfícies dos Nichos Personalizados: no; Tipo de Requadro (gs_reveal_type_new): Requadro Reto - Borda; Tipo de Requadro (gs_reveal_type_int): 1; Tipo de Requadro Base (gs_reveal_type_bottom): Requadro Reto; Tipo de Requadro Base (gs_reveal_type_bottom_int): 2; Definir Profund. Montante no Lado: 1; Profundidade Uniforme: yes; Tipo de Requadro Exterior: Requadro Reto; Tipo de Requadro (gs_reveal_doubleOuterTypeInt): 0; Tipo de Requadro Interior: Requadro Reto; Tipo de Requadro (gs_reveal_doubleInnerTypeInt): 0; Ângulo Lado 2: 20 deg; Ângulo Lado: 20 deg; Ângulo do Topo: 20 deg; Ângulo da Base: 20 deg; Ângulo Exterior Lado 2: 20 deg; Ângulo Exterior Lado: 20 deg; Ângulo Ext. Lado Superior: 20 deg; Ângulo Ext. Lado Inferior: 20 deg; Grade abaixo Folhas: no; Trilho (gs_door_rail_ext): Off; Trilho (gs_door_rail_ext_m): 1; Usar Componente de Acabamento: no; Auto Ligagem da Face Interna da Argamassa: yes; Ligar Face Interna da Argamassa: 0; Auto Ligagem da face Externa da Argamassa: yes; Ligar Face Externa da Argamassa: 0; Dimensionável em 2D: no; Mostrar em 3D: no; Tipo de Fechamento (gs_closure_type): Sem Fechamento; Tipo de Fechamento (gs_closure_type_int): 1; Dobrar Camada no Lado (gs_cavity_side): Ambas; Dobrar Camada no Lado (iCavityClosureSide): 1; No. de Camadas: 1; Numerar a partir de (gs_nTurnDir): Face externa; Numerar a partir de (iCavityClosureTurnDir): 1; Colocar Fechamento no Lado 1: yes; Colocar Fechamento no Lado 2: yes; Colocar Fechamento no Topo: no; Colocar Fechamento na Base: no; Colocar Fechamento para Camada: 1; Colocar Fechamento do Lado (gs_cc_dutch_ClosureToSide): 1; Fenda na Camada Externa: yes; Dobrar Camada para Encerram.: no; Inserir Camada de Isolamento: yes; Mostrar Camada de Isolamento: yes; Caneta de Contorno (gs_penJoint): Aberturas - Corte Não Estrutural; Tipo Linha Contorno (gs_ltJoint): 1; Tipo de Trama (gs_fillJoint): Isolamento 2; Caneta da Trama (gs_penJointFg): Geral - Geral; Caneta do Fundo da Trama (gs_penJointBg): Elementos 2D - Desenhos; Superfície Personalizada: no; Superfície: Madeira - Pinho Granulado Horizontal; Caneta de Contorno (gs_penPlug): Aberturas - Corte Não Estrutural; Tipo Linha Contorno (gs_ltPlug): 1; Tipo de Trama (gs_fillPlug): Isolamento 2; Caneta da Trama (gs_penPlugFg): Geral - Geral; Caneta do Fundo da Trama (gs_penPlugBg): Elementos 2D - Desenhos; Lado Ombreira Editado: 1; Lado Parede Editado: 1; Número de Camada Editado: 1; Camada que Dobra: no; Considerar Camada como Reboco: no; Espessura da Camada que Dobra: 1; Orientação Trama: 1; Linha Separa Camada que Dobra: no; Caneta Linha Separação: Geral - Geral; Último Lado Selecionado: no; Método de Fechamento Alterado Automaticamente: no; Conexão no Lado 1: no; Conexão no Lado 2: no; Conexão em Cima: no; Tipo Abertura (gs_leaf_optype): Preso Lateral; Tipo Abertura (gs_leaf_optype_m): 1; Abertura Painel Final Lado 1: no; Abertura Painel Final Lado 2: no; Ângulo Abertura 2D: 90 deg; Ângulo Abertura em 2D no Lado 2: 90 deg; Ângulo Abertura em 3D: 0 deg; Ângulo Abertura Terminação Painel em 3D Lado 2: 0 deg; Ângulo de Abertura Caixilho Principal Lado 1 (openingAngle_05): 0 deg; Ângulo de Abertura Caixilho Principal Lado 1 (openingAngle2_05): 0 deg; Ângulo de Abertura Caixilho Principal Lado 2 (openingAngle_09): 0 deg; Ângulo de Abertura Caixilho Principal Lado 2 (openingAngle2_09): 0 deg; Ângulo de Abertura Bandeira Meio (openingAngle_02): 0 deg; Ângulo de Abertura Bandeira Meio (openingAngle2_02): 0 deg; Ângulo de Abertura Bandeira Lado 1 (openingAngle_06): 0 deg; Ângulo de Abertura Bandeira Lado 1 (openingAngle2_06): 0 deg; Ângulo Abertura Bandeira Lado 2 (openingAngle_10): 0 deg; Ângulo Abertura Bandeira Lado 2 (openingAngle2_10): 0 deg; Tipo de Linha Duplo Sentido: 4; Substituir OVM para Visual. Simbólica 2D: no; Tipo Linha Abertura: 1; Forma da Linha de Abertura (or_SwingType): Curva; Forma da Linha de Abertura (or_iSwingType): 1; Forma da Linha de Abertura (or_SlidingType): Nenhum; Forma da Linha de Abertura (or_iSlidingType): 0; Mostrar Linha da Vidraça em 2D: yes; Caneta da Linha da Vidraça em 2D (or_iGlazingLinePen): 3; Caneta da Linha da Vidraça em 2D (or_glazingLinePen): Aberturas - Geral; Substituir OVM para Projeções 3D da Porta: no; Mostrar Linha de Abertura (or_bOplines3d): yes; Tipo Linha Lado da Abertura (or_opLineType3dIn): Linha Sólida; Tipo Linha Lado da Abertura (or_iOpLineType3dIn): 0; Tipo Linha Lado Oposto (or_opLineType3dOut): Linha Sólida; Tipo Linha Lado Oposto (or_iOpLineType3dOut): 0; Orientação da Linha (or_oplineStyle): Maçaneta; Orientação da Linha (or_iOplineStyle): 1; Caneta de Linha de Abertura em 2D/3D (or_opLinePen): Aberturas - Geral; Caneta de Linha de Abertura em 2D/3D (or_iOpLinePen): 3; Substituir OVM para Projeções 3D Luz Lateral/Bandeira: no; Mostrar Linha de Abertura (or_bWinOplines3d): yes; Tipo Linha Lado da Abertura (or_winOpLineType3dIn): Linha Sólida; Tipo Linha Lado da Abertura (or_iWinOpLineType3dIn): 0; Tipo Linha Lado Oposto (or_winOpLineType3dOut): Linha Sólida; Tipo Linha Lado Oposto (or_iWinOpLineType3dOut): 0; Orientação da Linha (or_winOplineStyle): Maçaneta; Orientação da Linha (or_iWinOplineStyle): 1; Caneta de Linha de Abertura em 2D/3D (or_winOpLinePen): Aberturas - Geral; Caneta de Linha de Abertura em 2D/3D (or_iWinOpLinePen): 3; Caneta Símbolo: Aberturas - Geral; Caneta Contorno Batente: Aberturas - Moldura; Caneta de Linha em Corte em Ambos os Lados da Guarnição: Aberturas - Geral; Caneta de Contorno Folha: Aberturas - Geral; Linha Contorno Parede (gs_wcont_line): Desligado; Linha Contorno Parede (iWallContourLine): 1; Tipo de Linha Interior Contorno Parede: 4; Tipo de Linha Exterior Contorno Parede: 4; Linha Interna Tracejada de Projeção Parede: 4; Linha Externa Tracejada de Projeção Parede: 4; Linha Contorno Luz Lateral Parede (gs_wcont_line_sl): Ambos Lados; Linha Contorno Luz Lateral Parede (iWallContourLineSl): 4; Tipo Linha Interior Contorno Luz Lateral Parede: 1; Tipo Linha Exterior Contorno Luz Lateral Parede: 1; Linha Interna Tracejada Projeção Parede Sobre Luz Lateral: 4; Linha Externa Tracejada Projeção Parede Sobre Luz Lateral: 4; Caneta Linha Contorno Parede: Aberturas - Geral; Tramas Usadas: yes; Tipo Trama Batente: Trama Vazia; Caneta Trama Batente: Aberturas - Fundo de Trama; Caneta Fundo Trama Batente: Fundos - Cor 1; Tipo Trama Folha: Ar (Vazio); Caneta Trama Folha: Aberturas - Fundo de Trama; Caneta Trama Fundo Folha: Fundos - Cor 1; Tipo de Trama do Símbolo Hermético: Trama Sólida; Caneta da Trama do Símbolo Hermético: Geral - Geral; Caneta de Fundo da Trama do Símbolo Hermético: Geral - Geral; Tipo Trama do Símbolo da Porta em Planta: Trama Vazia; Caneta da Trama do Símbolo da Porta em Planta: Fundos - Cor 1; Caneta de Fundo da Trama do Símbolo da Porta em Planta: Transparente; Tipo Trama Símbolo em Planta da Luz Lateral: Trama Vazia; Caneta Trama Símbolo em Planta da Luz Lateral: Fundos - Cor 1; Caneta Fundo Trama Símbolo em Planta da Luz Lateral: Fundos - Cor 1; Tipo de Linha de Degrau e Peitoril: 1; Pena de Contorno da Seção da Soleira: Aberturas - Geral; Tipo de Trama da Soleira em Corte: Trama Vazia; Caneta da Trama da Soleira em Corte: Fundos - Cor 1; Caneta da Trama de Fundo Seção Soleira: Fundos - Cor 1; Caneta de Vista e 3D da Peitoril: Geral - Geral; Caneta de Contorno de Corte Peitoril: Geral - Geral; Tipo de Trama Corte Peitoril: Trama Vazia; Caneta Trama do Parapeito em Corte: Fundos - Cor 1; Caneta de Fundo de Trama de Seção do Peitoril: Fundos - Cor 1; Caneta de Contorno Isolamento Seção: Geral - Geral; Tipo de Trama do Isolamento da Seção: Isolamento 2; Caneta Trama Isolamento Seção: Geral - Geral; Caneta da Trama de Fundo Isolamento Seção: Fundos - Cor 1; Caneta de Vista e 3D do Peitoril Interno: Geral - Geral; Caneta de Contorno Seção Peitoril Interno: Geral - Geral; Tipo de Trama do Peitoril Interno em Corte: Trama Vazia; Caneta Trama do Peitoril Interno em Corte: Fundos - Cor 1; Caneta Trama de Fundo do Peitoril Interno em Corte: Fundos - Cor 1; Tipo de Trama de Guarnição Int.: Trama Vazia; Caneta de Trama de Guarnição Int: Aberturas - Fundo de Trama; Caneta de Fundo de Trama de Guarnição Int: Fundos - Cor 1; Tipo de Trama de Guarnição Ext: Trama Vazia; Caneta de Trama de Guarnição Ext: Aberturas - Fundo de Trama; Caneta de Fundo de Trama de Guarnição Ext: Fundos - Cor 1; Tipo de Trama de Seção do Arco: Trama Vazia; Caneta da Trama da Seção do Arco: Fundos - Cor 1; Caneta de Fundo de Trama de Seção do Arco: Fundos - Cor 1; Tipo de Trama do Corte do Perfil da Ventilação: Ar (Vazio); Caneta da Trama do Corte do Perfil da Ventilação: Fundos - Cor 1; Caneta do Fundo da Trama do Corte do Perfil da Ventilação: Fundos - Cor 1; Tipo de Linha de Símbolo Quebra-Sol: 1; Caneta da Linha em Corte do Quebra-Sol: Geral - Geral; 3D/Caneta das Linhas não Cortadas no Corte: Aberturas - Geral; Tipo da Trama de Corte Quebra-Sol (gs_sunShade_cutFillType): Trama Vazia; Tipo da Trama de Corte Quebra-Sol (gs_sunShade_cutFillPen): Geral - Geral; Caneta da Trama do Fundo Corte Quebra-Sol: Fundo da Janela; Tipo Trama Isolamento Quebra-Sol: Trama Vazia; Caneta da Trama Isolamento Quebra-Sol: Geral - Geral; Caneta do Fundo Isolamento Quebra-Sol: Fundo da Janela; Tipo de Trama de Não-Cortado: Trama Vazia; Caneta da Trama de Não-Cortado: Elementos 2D - Geral; Caneta de Fundo da Trama Não-Cortado: Fundos - Cor 1; Valores Lado de Abertura (gs_opside_list): Pessoal; Valores Lado de Abertura (gs_opside_list_m): 0; Junção Elementos Batente (gs_SashText_typ): Travessa Sobrepõe Montante; Junção Elementos Batente (gs_SashText_typ_num): 2; Caneta Moldura: Aberturas - Geral; Caneta Folha: Aberturas - Geral; Caneta Caixilho de Vidro: Aberturas - Corte Não Estrutural; Caneta Vidro da Folha: Aberturas - Corte Não Estrutural; Caneta de Arco de Alvenaria: Paredes - Geral; Resolução Curva: 32; Sombra: yes; Superfície da Porta Uniforme: no; Batente Externo: Madeira - Pinho Granulado Horizontal; Batente Interno: Madeira - Pinho Granulado Horizontal; Folha Externa: Madeira - Pinho Granulado Horizontal; Folha Interna: Madeira - Pinho Granulado Horizontal; Folha 2: Madeira - Pinho Granulado Horizontal; Folha 3: Madeira - Pinho Granulado Horizontal; Trava: Pintura - Anthracite; Grelha Externa (gs_grill_mat): Madeira - Pinho Granulado Horizontal; Grelha Interna (gs_grill_mat2): Madeira - Pinho Granulado Horizontal; Grelha Externa (gs_leaf_grill_mat): Madeira - Pinho Granulado Horizontal; Grelha Interna (gs_leaf_grill_mat2): Madeira - Pinho Granulado Horizontal; Painel Sólido Exterior: Madeira - Pinho Granulado Horizontal; Painel Sólido Interior: Madeira - Pinho Granulado Horizontal; Caixilho de Vidro: Vidro - Simples; Folha de Vidro: Vidro - Simples; Trilho (gs_rail_mat): Metal - Ferro; Grelha Ventilação Externa: Madeira - Pinho Granulado Horizontal; Grelha Ventilação Interna: Madeira - Pinho Granulado Horizontal; Placa de Proteção: Metal - Alumínio; Superfícies Guarnição Uniformes: no; Interior Guarnição: Madeira - Pinho Granulado Horizontal; Exterior Guarnição: Madeira - Pinho Granulado Horizontal; Perfil de Ventilação: Metal - Alumínio; Painel Veneziana: Madeira - Pinho Granulado Horizontal; Moldura Painel Veneziana: Madeira - Pinho Granulado Horizontal; Caixa do Rolamento Veneziana: Metal - Aço Inoxidável; Lâminas Rolamento Veneziana: Pintura - Branco Titânio; Barras Rolamento Veneziana: Pintura - Branco Titânio; Caixa Persianas: Metal - Aço Inoxidável; Segmento Persianas: Pintura - Branco Titânio; Trilho Deslizante Veneziana: Metal - Aço Inoxidável; Soleira (gs_treshold_mat): Pedra - Granito Cinza; Soleira Metálica: Metal - Alumínio; Soleira/Peitoril (gs_sill_mat): Tijolo - Aparelho ao Comprido; Argamassa do Peitoril em Tijolo: Estuque - Branco Áspera; Peitoril Interno (gs_board_mat): Madeira - Pinho Granulado Horizontal; Maçaneta: Metal - Aço Inoxidável; Acessórios Maçaneta: Metal - Ferro; Proteção Borda Externa (matKickBoardOut): Metal - Aço Inoxidável; Proteção Borda Interna (matKickBoardIn): Metal - Aço Inoxidável; Arco de Alvenaria em Tijolo: Tijolo - Aparelho ao Comprido; Argamassa do Arco de Alvenaria: Estuque - Branco Áspera; Fecho Arco de Alvenaria: Pedra - Arenito 01; Nincho: Pintura - Óxido de Chumbo Amarelo; Etiquetas e Rótulos: 1; Mostrar Dimensões da Largura da Folha: yes; Mostrar ID Porta: no; Mostrar Texto Personalizado: yes; Texto Personalizado: <Texto Personalizado>; Sempre Legível: yes; Tipo Fonte: Arial; Tamanho Fonte: 2; Estilo Fonte: 0; Caneta Texto (iPenText): 1; Caneta Texto (penText): Geral - Geral; Porta pertence à Zona dentro da qual abre: yes; Custo: 0; Localização como: Nome do Compartimento; Área Total Envidraçada (gs_list_glassarea_tmp): 0; Substituir Área Envidraçada: yes; Área Total Envidraçada (gs_list_glassarea): 0; Perimetro Total Vidro: 0; Desempenho Ar Livre (mm2/l/m): 0; Tipo de Grupo (FM_Type): Outros; Tipo de Grupo (iFMType): 25; Peso Objeto: 0; Unidade Peso Objeto: kg; Definição Orientação Porta: 0; Orientação Porta: E; Fechamento de Porta: no; Tipo Painel Visor: Sem Painel Vision; Dispositivo Pega Abrir: no; Larguras de Folha da Porta: 0,72; Operação IFC (ifc_optypestr): Porta Simples Abertura Simples; Operação IFC (ifc_optype): 1
Name | Description | Tamanho Nominal L x A X E | Estrutura da Parede | ID do Elemento = ID do Elemento e Associação | Nome da Zona Relacionada = Até Zona | Número da Zona Relacionada = Até Número de Zona | ID Pai | Volume (m3) = NetVolume (m3) = Volume (Líquido) (m3) = Component, Volume Componente (Líquido) (m3) = Component, Volume do componente (Bruto) (m3) | Depth (mm) = Espessura da Parede (mm) = Espessura do Batente (mm) = Espessura Moldura Real (mm) | Abertura Volume de Vão L/D (m3) = P/J Volume Nominal da Abertura (m3) | Abertura Área da Superfície L/D (m2) = Área da Superfície (m2) = Área da Superfície da Base (Líquida) (m2) | Altura da Soleira/Peitoril ou Padieira (mm) = P/J Altura Nominal do Parapeito (mm) = P/J Altura do Parapeito no Lado do Requadro (mm) = P/J Altura do Parapeito no Lado Oposto do Requadro (mm) = Elevação à Origem do Projeto (mm) = Elevação ao 1º Nível de Referência (mm) = Elevação ao 2º Nível de Referência (mm) = Elevação ao Nível do Mar (mm) = Elevação ao Piso (mm) = Afastamento do Piso de Origem (mm) = Altura Peitoril ao Piso Atual (mm) | P/J Altura Nominal da Padieira (mm) = P/J Altura da Padiera no Lado Oposto do Requadro (mm) = P/J Altura da Padiera no Lado do Requadro (mm) | Elevação do Topo ao Primeiro Nível de Referência (mm) = Elevação do Topo Ao Piso de Origem (mm) = Elevação do Topo À Cota Zero (mm) = Elevação do Topo Ao Nível do Mar (mm) = Elevação do Topo Ao Segundo Nível de Referência (mm) | Elevação da Base Ao Primeiro Nível de Referência (mm) = Elevação da Base Ao Piso de Origem (mm) = Elevação da Base À Cota Zero (mm) = Elevação da Base Ao Nível do Mar (mm) = Elevação da Base Ao Segundo Nível de Referência (mm) | Direção da Abertura | Inserir o Valor do Parapeito da Parede
P05 | Porta-externa-genéricorta-interna-madeira-girar- 80cm x 210cm | 0,80×2,10×0,15 | Alvenaria 140, Rebocada 2 Faces | P05 | Dormitório 2 | 02 | Parede-05 | 0.0931503 | 150 | 0.252 | 6.98728 | 0 | 2100 | 2135 | -1.95331e-14 | 1 | 2 | AC_Pset_Porta_27 - Localização: Dormitório 2
P02 | Porta-interna-genérico-madeira-girar- 80cm x 210cm | 0,80×2,10×0,16 | Alvenaria 140, Rebocada + Azulejo | P02 | Banheiro | 03 | Parede-08 | 0.0956003 | 160 | 0.2688 | 7.08828 | 10 | 2110 | 2145 | 10 | 0 | 3 | ArchiCADProperties - Zonas em Colisão: Hall

# IfcOpeningElement (11)
In: Pavimento Térreo
Name | Depth (mm) | Height (mm) | Width (mm) | Area (m2) | Volume (m3)
J03 | 150 | 1200 | 1000 | 1.2 | 0.0543
J02 | 150 | 1200 | 1000 | 1.2 | 0.0362755
J05 | 150 | 1200 | 1000 | 1.2 | 0.0543
J04 | 150 | 1200 | 1000 | 1.2 | 0.0543
J06 | 160 | 800 | 800 | 0.64 | 0.0181695
J01 | 160 | 1200 | 1000 | 1.2 | 0.0245314
P04 | 150 | 2100 | 800 | 1.68 | 0.0931503
P03 | 150 | 2100 | 800 | 1.68 | 0.0931503
P05 | 150 | 2100 | 800 | 1.68 | 0.0931503
P01 | 150 | 2100 | 800 | 1.68 | 0.0583131
P02 | 160 | 2100 | 800 | 1.68 | 0.0956003

# IfcRoof, Cobert-01
In: Cobertura
Description: Cobertura-externa-inloco-telha_cerâmica-20cm; Classification: 3E 14 04 02 Telhado (NBR 15965-5 3E); Cobertura (Classificação Archicad); Material: Telha - Cobertura
Pset_RoofCommon - TotalArea: 88.1945 m2; IsExternal: yes
Pset_ManufacturerTypeInformation - ProductionYear: DD/MM/YYYY
ArchiCADProperties - Método de Geometria: Multi-Plano; Inclinação: 16.6992 deg; Corpo de Corte: Contornos Abaixo; ID do Elemento: Cobert-01; ID do Elemento e Associação: Cobert-01; Vegetal: ARQ - Cobertura; Material de Construção/ Composição / Perfil / Trama: Telha - Cobertura; Material de Construção: Telha - Cobertura; Protegido: no; Nome Piso de Origem: Cobertura; Número Piso de Origem: 1; Tipo de Elemento: Cobertura; Tipo: Básica; ID Pai: Cobert-01; Materiais de Construção (Todos): Telha - Cobertura; Superfícies (Todas): Madeira - Pinho Granulado Horizontal; Cobertura Telhas - Francesa Vermelho; Trama em Vista: Trama Vazia; Superfície da Borda: Madeira - Pinho Granulado Horizontal; Nome das Opções de Projeto: Modelo Principal; Nome do Conjunto de Opções de Projeto: Modelo Principal; Posição: Exterior; Mostrar em Filtro de Renovação: Todos os Filtros Relevantes; Função Estrutural: Elemento Estrutural; Estado de Renovação: Existente; Estado das Opções de Projeto: Modelo Principal; Conjunto de Opções de Projeto: Modelo Principal
Component Properties - Telha - Cobertura, Carbono Incorporado: 8466.67 (kgCO₂); Telha - Cobertura, Energia Incorporada: 105833 MJ; Telha - Cobertura, Tipo de Componente: Nenhum
Material Properties - Telha - Cobertura, ThermalConductivity: 1; Telha - Cobertura, SpecificHeatCapacity: 800 J/kg/K; Telha - Cobertura, MassDensity: 2000 kg/m3; Telha - Cobertura, Embodied Energy: 3 (MJ/kg); Telha - Cobertura, Embodied Carbon: 0.24 (kgCO₂/kg); Telha - Cobertura, Name: Telha - Cobertura; Telha - Cobertura, ID: VED; Telha - Cobertura, Participates in Collision Detection: yes
BaseQuantities - TotalSurfaceArea: 88.1945 m2
AC_Pset_RenovationAndPhasing - Renovation Status: Existing
ArchiCADQuantities - Comprimento da Conexão da Cúpula: 0 mm; Comprimento Beirais: 22288.1 mm; Comprimento da Conexão da Terminação da Parede: 0 mm; Comprimento Águas: 16808.9 mm; Área da Superfície da Base da Cobertura (Bruta): 88.1945 m2; Área da Superfície das Bordas da Cobertura (Bruta): 7.99727 m2; Área da Superfície do Topo da Cobertura (Bruta): 88.1945 m2; Comprimento Arestas: 0 mm; Área de Superfície dos Furos: 0 m2; Comprimento Ligação Concavidade: 0 mm; Área de Superfície da Base da Cobertura (Líquida): 88.1945 m2; Número de Furos: 0; Número de Claraboias: 0; Área de Superfície das Aberturas: 0 m2; Comprimento Cume Plano-Simples: 0 mm; Comprimento das Cumeeiras: 10100 mm; Comprimento da Conexão da Parede Lateral: 0 mm; Comprimento Águas-Furtadas: 0 mm; Espessura: 200 mm; Altura: 200 mm; Elevação à Origem do Projeto: 2615.45 mm; Elevação ao 1º Nível de Referência: 2615.45 mm; Elevação ao 2º Nível de Referência: 2615.45 mm; Elevação ao Nível do Mar: 2615.45 mm; Elevação ao Piso: 115.452 mm; Afastamento do Piso de Origem: 115.452 mm; Elevação do Topo ao Primeiro Nível de Referência: 3791.76 mm; Elevação do Topo Ao Piso de Origem: 1291.76 mm; Elevação do Topo À Cota Zero: 3791.76 mm; Elevação do Topo Ao Nível do Mar: 3791.76 mm; Elevação do Topo Ao Segundo Nível de Referência: 3791.76 mm; Elevação da Base Ao Primeiro Nível de Referência: 2075.45 mm; Elevação da Base Ao Piso de Origem: -424.548 mm; Elevação da Base À Cota Zero: 2075.45 mm; Elevação da Base Ao Nível do Mar: 2075.45 mm; Elevação da Base Ao Segundo Nível de Referência: 2075.45 mm
Component Quantities - Telha - Cobertura, Massa: 35277.8 kg; Telha - Cobertura, Área de Componente Projetada (Líquida): 89.4065 m2; Telha - Cobertura, Área de Componente Projetada (Bruta): 89.4065 m2; Telha - Cobertura, Área de Componente Projetada (Condicional): 0 m2; Telha - Cobertura, Espessura do Componente: 200 mm; Telha - Cobertura, Volume Componente (Líquido): 17.6389 m3; Telha - Cobertura, Volume do componente (Bruto): 17.6389 m3

# IfcSlab: Concreto 80, CP01
In: Cobertura
Type - PredefinedType: FLOOR
Description: Contrapiso-interno-inloco-concreto-8cm; Classification: 3E 16 02 02 Contrapiso (NBR 15965-5 3E); Contrapiso em Concreto (Classificação Archicad); Material: Concreto 80 mm
AC_Pset_RenovationAndPhasing - Renovation Status: Existing
Pset_SlabCommon - IsExternal: no; LoadBearing: no
ArchiCADProperties - Localização do Plano de Referência: Fundo; ID do Elemento: CP01; ID do Elemento e Associação: CP01; Vegetal: ARQ - Piso; Material de Construção/ Composição / Perfil / Trama: Concreto; Material de Construção: Concreto; Protegido: no; Nome Piso de Origem: Cobertura; Número Piso de Origem: 1; Tipo de Elemento: Laje; Tipo: Básica; ID Pai: CP01; Materiais de Construção (Todos): Concreto; Superfícies (Todas): Concreto - 01; Trama em Vista: Trama Vazia; Número de Aberturas: 0; Superfície do Topo: Concreto - 01; Superfície da Borda: Concreto - 01; Superfície da Base: Concreto - 01; Nome das Opções de Projeto: Modelo Principal; Nome do Conjunto de Opções de Projeto: Modelo Principal; Posição: Interior; Mostrar em Filtro de Renovação: Todos os Filtros Relevantes; Função Estrutural: Elemento Não-Estrutural; Estado de Renovação: Existente; Estado das Opções de Projeto: Modelo Principal; Conjunto de Opções de Projeto: Modelo Principal
Material Properties - Concreto, ThermalConductivity: 1.15; Concreto, SpecificHeatCapacity: 1000 J/kg/K; Concreto, MassDensity: 1800 kg/m3; Concreto, Embodied Energy: 0.74 (MJ/kg); Concreto, Embodied Carbon: 0.107 (kgCO₂/kg); Concreto, Name: Concreto; Concreto, ID: CON; Concreto, Participates in Collision Detection: yes
BaseQuantities - Width: 80 mm; Perimeter: 4220 mm; GrossArea: 1.071 m2; NetArea: 1.071 m2; GrossVolume: 0.08568 m3; NetVolume: 0.08568 m3
ArchiCADQuantities - Elevação da Base: 2580 mm; Área da Superfície do Topo da Laje (Condicional): 1.071 m2; Área da Superfície da Base da Laje (Bruta): 1.071 m2; Área da Superfície da Base da Laje (Bruta, com os furos): 1.071 m2; Área da Superfície das Bordas da Laje (Bruta): 0.3376 m2; Área da Superfície das Bordas da Laje (Bruta, com as bordas dos furos): 0.3376 m2; Área da Superfície do Topo da Laje (Bruta): 1.071 m2; Área da Superfície do Topo da Laje (Bruta, com os furos): 1.071 m2; Área de Superfície dos Furos: 0 m2; Topo da Elevação: 2660 mm; Área: 1.071 m2; Altura: 80 mm; Volume (Líquido): 0.08568 m3; Elevação à Origem do Projeto: 2580 mm; Elevação ao 1º Nível de Referência: 2580 mm; Elevação ao 2º Nível de Referência: 2580 mm; Elevação ao Nível do Mar: 2580 mm; Elevação ao Piso: 80 mm; Afastamento do Piso de Origem: 80 mm; Área da Superfície: 1.071 m2; Espessura: 80 mm; Volume (Condicional): 0.08568 m3; Volume (Bruto): 0.08568 m3; Perímetro na Planta: 4220 mm; Perímetro Furos da Planta: 0 mm; Elevação do Topo ao Primeiro Nível de Referência: 2660 mm; Elevação do Topo Ao Piso de Origem: 160 mm; Elevação do Topo À Cota Zero: 2660 mm; Elevação do Topo Ao Nível do Mar: 2660 mm; Elevação do Topo Ao Segundo Nível de Referência: 2660 mm; Elevação da Base Ao Primeiro Nível de Referência: 2580 mm; Elevação da Base Ao Piso de Origem: 80 mm; Elevação da Base À Cota Zero: 2580 mm; Elevação da Base Ao Nível do Mar: 2580 mm; Elevação da Base Ao Segundo Nível de Referência: 2580 mm; Área da Superfície do Topo (Líquida): 1.071 m2; Área da Superfície do Topo (Condicional): 1.071 m2; Área da Superfície da Borda (Líquida): 0.3376 m2; Área da Superfície da Base (Líquida): 1.071 m2; Área da Superfície da Base (Condicional): 1.071 m2; Área da Superfície da Base (Bruta): 1.071 m2; Área da Superfície das Bordas (Bruta): 0.3376 m2; Área da Superfície do Topo (Bruta): 1.071 m2
Component Quantities - Concreto, Massa: 154.224 kg; Concreto, Área de Componente Projetada (Líquida): 1.071 m2; Concreto, Área de Componente Projetada (Bruta): 1.071 m2; Concreto, Área de Componente Projetada (Condicional): 1.071 m2; Concreto, Espessura do Componente: 80 mm; Concreto, Volume Componente (Líquido): 0.08568 m3; Concreto, Volume do componente (Bruto): 0.08568 m3; Concreto, Volume Componente (Condicional): 0.08568 m3
Component Properties - Concreto, Carbono Incorporado: 16.502 (kgCO₂); Concreto, Energia Incorporada: 114.126 MJ; Concreto, Tipo de Componente: Nenhum

# IfcSlab: Concreto Armado - Estrutural 200, F01
In: Fundação
Description: Fundação_radier-externa-inloco-concreto_armado-20cm; Classification: Laje (Classificação Archicad); 3E 10 02 Elementos de fundações diretas (NBR 15965-5 3E); Material: Concreto Armado - Estrutural 200 mm
ArchiCADProperties - Localização do Plano de Referência: Fundo; Geração do Modelo Analítico Estrutural: yes; Geometria do Membro Editada Manualmente: no; ID do Elemento: F01; ID do Elemento e Associação: F01; Vegetal: EST - Laje; Material de Construção/ Composição / Perfil / Trama: Concreto Armado - Estrutural; Material de Construção: Concreto Armado - Estrutural; Protegido: no; Nome Piso de Origem: Fundação; Número Piso de Origem: -1; Tipo de Elemento: Laje; Tipo: Básica; ID Pai: F01; Materiais de Construção (Todos): Concreto Armado - Estrutural; Superfícies (Todas): Concreto - 03; Trama em Vista: Trama Vazia; Número de Aberturas: 0; Superfície do Topo: Concreto - 03; Superfície da Borda: Concreto - 03; Superfície da Base: Concreto - 03; Nome das Opções de Projeto: Modelo Principal; Nome do Conjunto de Opções de Projeto: Modelo Principal; Posição: Exterior; Mostrar em Filtro de Renovação: Todos os Filtros Relevantes; Função Estrutural: Elemento Estrutural; Estado de Renovação: Existente; Estado das Opções de Projeto: Modelo Principal; Conjunto de Opções de Projeto: Modelo Principal
Pset_ManufacturerTypeInformation - ProductionYear: DD/MM/YYYY
Pset_SlabCommon - IsExternal: yes; LoadBearing: yes
AC_Pset_RenovationAndPhasing - Renovation Status: Existing
Component Properties - Concreto Armado - Estrutural, Carbono Incorporado: 10720.8 (kgCO₂); Concreto Armado - Estrutural, Energia Incorporada: 103221 MJ; Concreto Armado - Estrutural, Tipo de Componente: Nenhum
Material Properties - Concreto Armado - Estrutural, ThermalConductivity: 2.5; Concreto Armado - Estrutural, SpecificHeatCapacity: 1000 J/kg/K; Concreto Armado - Estrutural, MassDensity: 2400 kg/m3; Concreto Armado - Estrutural, Embodied Energy: 2.33 (MJ/kg); Concreto Armado - Estrutural, Embodied Carbon: 0.242 (kgCO₂/kg); Concreto Armado - Estrutural, Name: Concreto Armado - Estrutural; Concreto Armado - Estrutural, ID: CON; Concreto Armado - Estrutural, Participates in Collision Detection: yes
ArchiCADQuantities - Elevação da Base: -280 mm; Área da Superfície do Topo da Laje (Condicional): 92.2936 m2; Área da Superfície da Base da Laje (Bruta): 92.2936 m2; Área da Superfície da Base da Laje (Bruta, com os furos): 92.2936 m2; Área da Superfície das Bordas da Laje (Bruta): 7.98 m2; Área da Superfície das Bordas da Laje (Bruta, com as bordas dos furos): 7.98 m2; Área da Superfície do Topo da Laje (Bruta): 92.2936 m2; Área da Superfície do Topo da Laje (Bruta, com os furos): 92.2936 m2; Área de Superfície dos Furos: 0 m2; Topo da Elevação: -80 mm; Área: 92.2936 m2; Altura: 200 mm; Volume (Líquido): 18.4587 m3; Elevação à Origem do Projeto: -280 mm; Elevação ao 1º Nível de Referência: -280 mm; Elevação ao 2º Nível de Referência: -280 mm; Elevação ao Nível do Mar: -280 mm; Elevação ao Piso: 0 mm; Afastamento do Piso de Origem: 0 mm; Área da Superfície: 92.2936 m2; Espessura: 200 mm; Volume (Condicional): 18.4587 m3; Volume (Bruto): 18.4587 m3; Perímetro na Planta: 39900 mm; Perímetro Furos da Planta: 0 mm; Elevação do Topo ao Primeiro Nível de Referência: -80 mm; Elevação do Topo Ao Piso de Origem: 200 mm; Elevação do Topo À Cota Zero: -80 mm; Elevação do Topo Ao Nível do Mar: -80 mm; Elevação do Topo Ao Segundo Nível de Referência: -80 mm; Elevação da Base Ao Primeiro Nível de Referência: -280 mm; Elevação da Base Ao Piso de Origem: 0 mm; Elevação da Base À Cota Zero: -280 mm; Elevação da Base Ao Nível do Mar: -280 mm; Elevação da Base Ao Segundo Nível de Referência: -280 mm; Área da Superfície do Topo (Líquida): 92.2936 m2; Área da Superfície do Topo (Condicional): 92.2936 m2; Área da Superfície da Borda (Líquida): 7.98 m2; Área da Superfície da Base (Líquida): 92.2936 m2; Área da Superfície da Base (Condicional): 92.2936 m2; Área da Superfície da Base (Bruta): 92.2936 m2; Área da Superfície das Bordas (Bruta): 7.98 m2; Área da Superfície do Topo (Bruta): 92.2936 m2
Component Quantities - Concreto Armado - Estrutural, Massa: 44300.9 kg; Concreto Armado - Estrutural, Área de Componente Projetada (Líquida): 92.2936 m2; Concreto Armado - Estrutural, Área de Componente Projetada (Bruta): 92.2936 m2; Concreto Armado - Estrutural, Área de Componente Projetada (Condicional): 92.2936 m2; Concreto Armado - Estrutural, Espessura do Componente: 200 mm; Concreto Armado - Estrutural, Volume Componente (Líquido): 18.4587 m3; Concreto Armado - Estrutural, Volume do componente (Bruto): 18.4587 m3; Concreto Armado - Estrutural, Volume Componente (Condicional): 18.4587 m3
BaseQuantities - Width: 200 mm; Perimeter: 39900 mm; GrossArea: 92.2936 m2; NetArea: 92.2936 m2; GrossVolume: 18.4587 m3; NetVolume: 18.4587 m3

# IfcSlab: Concreto Armado - Estrutural 80 (2)
Description: Laje-interna-inloco-concreto_armado-8cm; Classification: Laje (Classificação Archicad); 3E 12 06 08 Laje (NBR 15965-5 3E); Material: Concreto Armado - Estrutural 80 mm
Pset_ManufacturerTypeInformation - ProductionYear: DD/MM/YYYY
AC_Pset_RenovationAndPhasing - Renovation Status: Existing
ArchiCADProperties - Geração do Modelo Analítico Estrutural: yes; Geometria do Membro Editada Manualmente: no; Vegetal: EST - Laje; Material de Construção/ Composição / Perfil / Trama: Concreto Armado - Estrutural; Material de Construção: Concreto Armado - Estrutural; Protegido: no; Tipo de Elemento: Laje; Tipo: Básica; Materiais de Construção (Todos): Concreto Armado - Estrutural; Superfícies (Todas): Concreto - 03; Trama em Vista: Trama Vazia; Número de Aberturas: 0; Superfície do Topo: Concreto - 03; Superfície da Borda: Concreto - 03; Superfície da Base: Concreto - 03; Nome das Opções de Projeto: Modelo Principal; Nome do Conjunto de Opções de Projeto: Modelo Principal; Posição: Interior; Mostrar em Filtro de Renovação: Todos os Filtros Relevantes; Função Estrutural: Elemento Estrutural; Estado de Renovação: Existente; Estado das Opções de Projeto: Modelo Principal; Conjunto de Opções de Projeto: Modelo Principal
Pset_SlabCommon - IsExternal: no; LoadBearing: yes
Material Properties - Concreto Armado - Estrutural, ThermalConductivity: 2.5; Concreto Armado - Estrutural, SpecificHeatCapacity: 1000 J/kg/K; Concreto Armado - Estrutural, MassDensity: 2400 kg/m3; Concreto Armado - Estrutural, Embodied Energy: 2.33 (MJ/kg); Concreto Armado - Estrutural, Embodied Carbon: 0.242 (kgCO₂/kg); Concreto Armado - Estrutural, Name: Concreto Armado - Estrutural; Concreto Armado - Estrutural, ID: CON; Concreto Armado - Estrutural, Participates in Collision Detection: yes
Component Properties - Concreto Armado - Estrutural, Tipo de Componente: Nenhum
ArchiCADQuantities - Área de Superfície dos Furos: 0 m2; Altura: 80 mm; Elevação ao Piso: 0 mm; Afastamento do Piso de Origem: 0 mm; Espessura: 80 mm; Perímetro Furos da Planta: 0 mm
BaseQuantities - Width: 80 mm
Component Quantities - Concreto Armado - Estrutural, Espessura do Componente: 80 mm
Name | In | Localização do Plano de Referência | ID do Elemento = ID do Elemento e Associação = ID Pai | Nome Piso de Origem | Número Piso de Origem | Concreto Armado - Estrutural, Carbono Incorporado | Concreto Armado - Estrutural, Energia Incorporada (MJ) | Elevação da Base (mm) = Elevação da Base Ao Primeiro Nível de Referência (mm) = Elevação da Base À Cota Zero (mm) = Elevação da Base Ao Nível do Mar (mm) = Elevação da Base Ao Segundo Nível de Referência (mm) | Área da Superfície do Topo da Laje (Condicional) (m2) = Área da Superfície da Base da Laje (Bruta) (m2) = Área da Superfície da Base da Laje (Bruta, com os furos) (m2) = Área da Superfície do Topo da Laje (Bruta) (m2) = Área da Superfície do Topo da Laje (Bruta, com os furos) (m2) = Área (m2) = Área da Superfície (m2) = Área da Superfície do Topo (Líquida) (m2) = Área da Superfície do Topo (Condicional) (m2) = Área da Superfície da Base (Líquida) (m2) = Área da Superfície da Base (Condicional) (m2) = Área da Superfície da Base (Bruta) (m2) = Área da Superfície do Topo (Bruta) (m2) = GrossArea (m2) = NetArea (m2) = Concreto Armado - Estrutural, Área de Componente Projetada (Líquida) (m2) = Concreto Armado - Estrutural, Área de Componente Projetada (Bruta) (m2) = Concreto Armado - Estrutural, Área de Componente Projetada (Condicional) (m2) | Área da Superfície das Bordas da Laje (Bruta) (m2) = Área da Superfície das Bordas da Laje (Bruta, com as bordas dos furos) (m2) = Área da Superfície da Borda (Líquida) (m2) = Área da Superfície das Bordas (Bruta) (m2) | Topo da Elevação (mm) = Elevação do Topo ao Primeiro Nível de Referência (mm) = Elevação do Topo À Cota Zero (mm) = Elevação do Topo Ao Nível do Mar (mm) = Elevação do Topo Ao Segundo Nível de Referência (mm) | Volume (Líquido) (m3) = Volume (Condicional) (m3) = Volume (Bruto) (m3) = GrossVolume (m3) = NetVolume (m3) = Concreto Armado - Estrutural, Volume Componente (Líquido) (m3) = Concreto Armado - Estrutural, Volume do componente (Bruto) (m3) = Concreto Armado - Estrutural, Volume Componente (Condicional) (m3) | Elevação à Origem do Projeto (mm) = Elevação ao 1º Nível de Referência (mm) = Elevação ao 2º Nível de Referência (mm) = Elevação ao Nível do Mar (mm) | Perímetro na Planta (mm) = Perimeter (mm) | Elevação do Topo Ao Piso de Origem (mm) | Elevação da Base Ao Piso de Origem (mm) | Concreto Armado - Estrutural, Massa (kg)
L01 | Pavimento Térreo | Topo | L01 | Pavimento Térreo | 0 | 2547.39 (kgCO₂) | 24526.5 | -80 | 54.825 | 2.392 | 0 | 4.386 | 0 | 29900 | 0 | -80 | 10526.4 | ArchiCADProperties - Nome da Zona Relacionada: Dormitório 1; Número da Zona Relacionada: 01
L02 | Cobertura | Fundo | L02 | Cobertura | 1 | 1303.32 (kgCO₂) | 12548.4 | 2500 | 28.05 | 1.888 | 2580 | 2.244 | 2500 | 23600 | 80 | 0 | 5385.6

# IfcSlab: Madeiramento - Cobertura 50 (4)
In: Cobertura
Description: Placa-interna-inloco-madeira-30x30cm; Classification: Placa (Classificação Archicad); 3E 12 08 02 Estrutura de placas (NBR 15965-5 3E); Material: Madeiramento - Cobertura 50 mm
Pset_ManufacturerTypeInformation - ProductionYear: DD/MM/YYYY
ArchiCADProperties - Localização do Plano de Referência: Fundo; Geração do Modelo Analítico Estrutural: yes; Geometria do Membro Editada Manualmente: no; Vegetal: ARQ - Piso; Material de Construção/ Composição / Perfil / Trama: Madeiramento - Cobertura; Material de Construção: Madeiramento - Cobertura; Protegido: no; Nome Piso de Origem: Cobertura; Número Piso de Origem: 1; Tipo de Elemento: Laje; Tipo: Básica; Materiais de Construção (Todos): Madeiramento - Cobertura; Superfícies (Todas): Madeira - Pinho Granulado Horizontal; Trama em Vista: Trama Vazia; Número de Aberturas: 0; Superfície do Topo: Madeira - Pinho Granulado Horizontal; Superfície da Borda: Madeira - Pinho Granulado Horizontal; Superfície da Base: Madeira - Pinho Granulado Horizontal; Nome das Opções de Projeto: Modelo Principal; Nome do Conjunto de Opções de Projeto: Modelo Principal; Posição: Interior; Mostrar em Filtro de Renovação: Todos os Filtros Relevantes; Função Estrutural: Elemento Estrutural; Estado de Renovação: Existente; Estado das Opções de Projeto: Modelo Principal; Conjunto de Opções de Projeto: Modelo Principal
Pset_SlabCommon - IsExternal: no; LoadBearing: yes
Component Properties - Madeiramento - Cobertura, Carbono Incorporado: 0.81 (kgCO₂); Madeiramento - Cobertura, Energia Incorporada: 22.5 MJ; Madeiramento - Cobertura, Tipo de Componente: Nenhum
BaseQuantities - Width: 50 mm; Perimeter: 1200 mm; GrossArea: 0.09 m2; NetArea: 0.09 m2; GrossVolume: 0.0045 m3; NetVolume: 0.0045 m3
AC_Pset_RenovationAndPhasing - Renovation Status: Existing
ArchiCADQuantities - Elevação da Base: 2580 mm; Área da Superfície do Topo da Laje (Condicional): 0.09 m2; Área da Superfície da Base da Laje (Bruta): 0.09 m2; Área da Superfície da Base da Laje (Bruta, com os furos): 0.09 m2; Área da Superfície das Bordas da Laje (Bruta): 0.06 m2; Área da Superfície das Bordas da Laje (Bruta, com as bordas dos furos): 0.06 m2; Área da Superfície do Topo da Laje (Bruta): 0.09 m2; Área da Superfície do Topo da Laje (Bruta, com os furos): 0.09 m2; Área de Superfície dos Furos: 0 m2; Topo da Elevação: 2630 mm; Área: 0.09 m2; Altura: 50 mm; Volume (Líquido): 0.0045 m3; Elevação à Origem do Projeto: 2580 mm; Elevação ao 1º Nível de Referência: 2580 mm; Elevação ao 2º Nível de Referência: 2580 mm; Elevação ao Nível do Mar: 2580 mm; Elevação ao Piso: 80 mm; Afastamento do Piso de Origem: 80 mm; Área da Superfície: 0.09 m2; Espessura: 50 mm; Volume (Condicional): 0.0045 m3; Volume (Bruto): 0.0045 m3; Perímetro na Planta: 1200 mm; Perímetro Furos da Planta: 0 mm; Elevação do Topo ao Primeiro Nível de Referência: 2630 mm; Elevação do Topo Ao Piso de Origem: 130 mm; Elevação do Topo À Cota Zero: 2630 mm; Elevação do Topo Ao Nível do Mar: 2630 mm; Elevação do Topo Ao Segundo Nível de Referência: 2630 mm; Elevação da Base Ao Primeiro Nível de Referência: 2580 mm; Elevação da Base Ao Piso de Origem: 80 mm; Elevação da Base À Cota Zero: 2580 mm; Elevação da Base Ao Nível do Mar: 2580 mm; Elevação da Base Ao Segundo Nível de Referência: 2580 mm; Área da Superfície do Topo (Líquida): 0.09 m2; Área da Superfície do Topo (Condicional): 0.09 m2; Área da Superfície da Borda (Líquida): 0.06 m2; Área da Superfície da Base (Líquida): 0.09 m2; Área da Superfície da Base (Condicional): 0.09 m2; Área da Superfície da Base (Bruta): 0.09 m2; Área da Superfície das Bordas (Bruta): 0.06 m2; Área da Superfície do Topo (Bruta): 0.09 m2
Component Quantities - Madeiramento - Cobertura, Massa: 2.25 kg; Madeiramento - Cobertura, Área de Componente Projetada (Líquida): 0.09 m2; Madeiramento - Cobertura, Área de Componente Projetada (Bruta): 0.09 m2; Madeiramento - Cobertura, Espessura do Componente: 50 mm; Madeiramento - Cobertura, Volume Componente (Líquido): 0.0045 m3; Madeiramento - Cobertura, Volume do componente (Bruto): 0.0045 m3
Material Properties - Madeiramento - Cobertura, ThermalConductivity: 0.14; Madeiramento - Cobertura, SpecificHeatCapacity: 2300 J/kg/K; Madeiramento - Cobertura, MassDensity: 500 kg/m3; Madeiramento - Cobertura, Embodied Energy: 10 (MJ/kg); Madeiramento - Cobertura, Embodied Carbon: 0.36 (kgCO₂/kg); Madeiramento - Cobertura, Name: Madeiramento - Cobertura; Madeiramento - Cobertura, ID: MAD; Madeiramento - Cobertura, Participates in Collision Detection: yes
Name | ID do Elemento = ID do Elemento e Associação = ID Pai
PL03 | PL03
PL02 | PL02
PL04 | PL04
PL01 | PL01

# IfcWall: Alvenaria 140, Azulejo + Azulejo 165, Parede-07 - Trecho 1
In: Pavimento Térreo
Description: Parede-interna-inloco-bloco_concreto-estrutural_com_revestimento-15cm; Classification: Parede (Classificação Archicad); 3E 14 02 00 Parede (NBR 15965-5 3E)
Pset_WallCommon - AcousticRating: 0,00; IsExternal: no; LoadBearing: yes
ArchiCADProperties - Complexidade da Parede: Retas; Método de Geometria: Uniforme; Localização da Linha de Referência: Face Interna; Superfície da Face Interna: Ladrilhos - Branco Mate15x15; Superfície da Face Externa: Ladrilhos - Branco Mate15x15; Ângulo de Inclinação Interno Parede: 90 deg; Ângulo de Inclinação Externo Parede: 90 deg; Geração do Modelo Analítico Estrutural: yes; Geometria do Membro Editada Manualmente: no; ID do Elemento: Parede-07 - Trecho 1; ID do Elemento e Associação: Parede-07 - Trecho 1; Vegetal: ARQ - Parede; Material de Construção/ Composição / Perfil / Trama: Alvenaria 140, Azulejo + Azulejo; Composições: Alvenaria 140, Azulejo + Azulejo; Nome da Zona Relacionada: Banheiro; Número da Zona Relacionada: 03; Protegido: no; Nome Piso de Origem: Pavimento Térreo; Número Piso de Origem: 0; Tipo de Elemento: Parede; Ponto de Vínculo do Piso Absoluto: Não Vinculado; Ponto de Vínculo do Piso Relativo: Não Vinculado; Vínculo Superior do Piso: Não Vinculado; Tipo: Composto; ID Pai: Parede-07 - Trecho 1; Materiais de Construção (Todos): Azulejo DEF; Argamassa Colante DEF; Bloco de Concreto - Estrutural DEF; Argamassa Colante DEF; Azulejo DEF; Superfícies (Todas): Pintura - Cinza Claro; Ladrilhos - Branco Mate15x15; Blocos de Concreto - Aparelho ao Comprido; Ângulo de Inclinação: 90 deg; Número de Aberturas: 0; Nome das Opções de Projeto: Modelo Principal; Nome do Conjunto de Opções de Projeto: Modelo Principal; Posição: Interior; Mostrar em Filtro de Renovação: Todos os Filtros Relevantes; Função Estrutural: Elemento Estrutural; Estado de Renovação: Existente; Estado das Opções de Projeto: Modelo Principal; Conjunto de Opções de Projeto: Modelo Principal
AC_Pset_RenovationAndPhasing - Renovation Status: Existing
ArchiCADQuantities - Número de Portas: 0; Número de Furos (Número de Aberturas Vazias): 0; Número de Janelas: 0; Número de Pilares: 0; Volume dos Pilares: 0 m3; Altura Máxima da Camada da Parede na Face Interna: 2500 mm; Altura Mínima da Camada da Parede na Face Interna: 2500 mm; Altura máxima da parede: 2500 mm; Altura mínima da parede: 2500 mm; Altura Máxima da Camada da Parede na Face Externa: 2500 mm; Altura Mínima da Camada da Parede na Face Externa: 2500 mm; Espessura da Camada de Ar: 0 mm; Área das Portas: 0 m2; Soma das Larguras das Portas: 0 mm; Espessura do Componente na Face Interna da Parede: 5 mm; Espessura do Componentena na Face Externa da Parede: 5 mm; Área das Janelas: 0 m2; Soma das Larguras das Janelas: 0 mm; Volume do Componente na Face Interna da Parede (Líquido): 0.025 m3; Volume do Componente na Face Externa da Parede (Líquido): 0.025 m3; Área Analítica da Superfície das Aberturas da Face Interna: 0 m2; Área Analítica da Superfície das Aberturas da Face Externa: 0 m2; Comprimento Médio da Parede: 2000 mm; Área da Superfície da Face Interna da Parede (Líquida): 5 m2; Área da Superfície da Face Externa da Parede (Líquida): 5 m2; Volume Analítico das Aberturas: 0 m3; Comprimento da Linha de Referência: 2000 mm; Comprimento da Face Interna da Parede (Condicional): 2000 mm; Área da Superfície da Face Interna da Parede (Condicional): 5 m2; Comprimento da Face Externa da Parede (Condicional): 2000 mm; Área da Superfície da Face Externa da Parede (Condicional): 5 m2; Volume do Componente da Face Interna da Parede (Condicional): 0.025 m3; Volume do Componente da Face Externa da Parede (Condicional): 0.025 m3; Área da Superfície da Face Interna da Parede (Bruta): 5 m2; Área da Superfície da Face Externa da Parede (Bruta): 5 m2; Espessura da Parede na Terminação: 165 mm; Comprimento da parede no centro: 2000 mm; Comprimento da Parede na Face Interna: 2000 mm; Comprimento da Parede na Face Externa: 2000 mm; Área de Superfície do Vão na Parede: 0 m2; Área: 0.33 m2; Altura: 2500 mm; Volume (Líquido): 0.825 m3; Largura: 165 mm; Elevação à Origem do Projeto: 0 mm; Elevação ao 1º Nível de Referência: 0 mm; Elevação ao 2º Nível de Referência: 0 mm; Elevação ao Nível do Mar: 0 mm; Elevação ao Piso: 0 mm; Afastamento do Piso de Origem: 0 mm; Afastamento do Topo: 0 mm; Área da Superfície: 5 m2; Comprimento 3D: 2000 mm; Espessura: 165 mm; Volume (Condicional): 0.825 m3; Volume (Bruto): 0.825 m3; Espessura da Camada de Isolamento: 0 mm; Perímetro na Planta: 4330 mm; Elevação do Topo ao Primeiro Nível de Referência: 2500 mm; Elevação do Topo Ao Piso de Origem: 2500 mm; Elevação do Topo À Cota Zero: 2500 mm; Elevação do Topo Ao Nível do Mar: 2500 mm; Elevação do Topo Ao Segundo Nível de Referência: 2500 mm; Elevação da Base Ao Primeiro Nível de Referência: 0 mm; Elevação da Base Ao Piso de Origem: 0 mm; Elevação da Base À Cota Zero: 0 mm; Elevação da Base Ao Nível do Mar: 0 mm; Elevação da Base Ao Segundo Nível de Referência: 0 mm; Área da Superfície do Topo (Líquida): 0.33 m2; Área da Superfície da Borda (Líquida): 1.485 m2; Área da Superfície da Base (Líquida): 5 m2
BaseQuantities - Length: 2000 mm; Height: 2500 mm; Width: 165 mm; GrossFootprintArea: 0.33 m2; NetFootprintArea: 0.33 m2; GrossSideArea: 5 m2; NetSideArea: 5 m2; GrossVolume: 0.825 m3; NetVolume: 0.825 m3

# IfcWall: Alvenaria 140, Azulejo + Rebocada 160, Parede-07 - Trecho 2
In: Pavimento Térreo
Description: Parede-interna-inloco-bloco_concreto-estrutural_com_revestimento-15cm; Classification: Parede (Classificação Archicad); 3E 14 02 00 Parede (NBR 15965-5 3E)
Pset_WallCommon - AcousticRating: 0,00; IsExternal: no; LoadBearing: yes
AC_Pset_RenovationAndPhasing - Renovation Status: Existing
ArchiCADProperties - Complexidade da Parede: Retas; Método de Geometria: Uniforme; Localização da Linha de Referência: Face Interna; Superfície da Face Interna: Ladrilhos - Branco Mate15x15; Superfície da Face Externa: Estuque - Branco Suave; Ângulo de Inclinação Interno Parede: 90 deg; Ângulo de Inclinação Externo Parede: 90 deg; Geração do Modelo Analítico Estrutural: yes; Geometria do Membro Editada Manualmente: no; ID do Elemento: Parede-07 - Trecho 2; ID do Elemento e Associação: Parede-07 - Trecho 2; Vegetal: ARQ - Parede; Material de Construção/ Composição / Perfil / Trama: Alvenaria 140, Azulejo + Rebocada; Composições: Alvenaria 140, Azulejo + Rebocada; Nome da Zona Relacionada: Hall; Número da Zona Relacionada: 04; Protegido: no; Nome Piso de Origem: Pavimento Térreo; Número Piso de Origem: 0; Tipo de Elemento: Parede; Ponto de Vínculo do Piso Absoluto: Não Vinculado; Ponto de Vínculo do Piso Relativo: Não Vinculado; Vínculo Superior do Piso: Não Vinculado; Tipo: Composto; ID Pai: Parede-07 - Trecho 2; Materiais de Construção (Todos): Reboco DEF; Bloco de Concreto - Estrutural DEF; Argamassa Colante DEF; Azulejo DEF; Superfícies (Todas): Estuque - Branco Suave; Pintura - Cinza Claro; Ladrilhos - Branco Mate15x15; Blocos de Concreto - Aparelho ao Comprido; Ângulo de Inclinação: 90 deg; Número de Aberturas: 0; Nome das Opções de Projeto: Modelo Principal; Nome do Conjunto de Opções de Projeto: Modelo Principal; Posição: Interior; Mostrar em Filtro de Renovação: Todos os Filtros Relevantes; Função Estrutural: Elemento Estrutural; Estado de Renovação: Existente; Estado das Opções de Projeto: Modelo Principal; Conjunto de Opções de Projeto: Modelo Principal
BaseQuantities - Length: 150 mm; Height: 2500 mm; Width: 160 mm; GrossFootprintArea: 0.024 m2; NetFootprintArea: 0.024 m2; GrossSideArea: 0.375 m2; NetSideArea: 0.375 m2; GrossVolume: 0.06 m3; NetVolume: 0.06 m3
ArchiCADQuantities - Número de Portas: 0; Número de Furos (Número de Aberturas Vazias): 0; Número de Janelas: 0; Número de Pilares: 0; Volume dos Pilares: 0 m3; Altura Máxima da Camada da Parede na Face Interna: 2500 mm; Altura Mínima da Camada da Parede na Face Interna: 2500 mm; Altura máxima da parede: 2500 mm; Altura mínima da parede: 2500 mm; Altura Máxima da Camada da Parede na Face Externa: 2500 mm; Altura Mínima da Camada da Parede na Face Externa: 2500 mm; Espessura da Camada de Ar: 0 mm; Área das Portas: 0 m2; Soma das Larguras das Portas: 0 mm; Espessura do Componente na Face Interna da Parede: 5 mm; Espessura do Componentena na Face Externa da Parede: 5 mm; Área das Janelas: 0 m2; Soma das Larguras das Janelas: 0 mm; Volume do Componente na Face Interna da Parede (Líquido): 0.001875 m3; Volume do Componente na Face Externa da Parede (Líquido): 0.001875 m3; Área Analítica da Superfície das Aberturas da Face Interna: 0 m2; Área Analítica da Superfície das Aberturas da Face Externa: 0 m2; Comprimento Médio da Parede: 150 mm; Área da Superfície da Face Interna da Parede (Líquida): 0.375 m2; Área da Superfície da Face Externa da Parede (Líquida): 0.375 m2; Volume Analítico das Aberturas: 0 m3; Comprimento da Linha de Referência: 150 mm; Comprimento da Face Interna da Parede (Condicional): 150 mm; Área da Superfície da Face Interna da Parede (Condicional): 0.375 m2; Comprimento da Face Externa da Parede (Condicional): 150 mm; Área da Superfície da Face Externa da Parede (Condicional): 0.375 m2; Volume do Componente da Face Interna da Parede (Condicional): 0.001875 m3; Volume do Componente da Face Externa da Parede (Condicional): 0.001875 m3; Área da Superfície da Face Interna da Parede (Bruta): 0.375 m2; Área da Superfície da Face Externa da Parede (Bruta): 0.375 m2; Espessura da Parede na Terminação: 160 mm; Comprimento da parede no centro: 150 mm; Comprimento da Parede na Face Interna: 150 mm; Comprimento da Parede na Face Externa: 150 mm; Área de Superfície do Vão na Parede: 0 m2; Área: 0.024 m2; Altura: 2500 mm; Volume (Líquido): 0.06 m3; Largura: 160 mm; Elevação à Origem do Projeto: 0 mm; Elevação ao 1º Nível de Referência: 0 mm; Elevação ao 2º Nível de Referência: 0 mm; Elevação ao Nível do Mar: 0 mm; Elevação ao Piso: 0 mm; Afastamento do Piso de Origem: 0 mm; Afastamento do Topo: 0 mm; Área da Superfície: 0.375 m2; Comprimento 3D: 150 mm; Espessura: 160 mm; Volume (Condicional): 0.06 m3; Volume (Bruto): 0.06 m3; Espessura da Camada de Isolamento: 0 mm; Perímetro na Planta: 620 mm; Elevação do Topo ao Primeiro Nível de Referência: 2500 mm; Elevação do Topo Ao Piso de Origem: 2500 mm; Elevação do Topo À Cota Zero: 2500 mm; Elevação do Topo Ao Nível do Mar: 2500 mm; Elevação do Topo Ao Segundo Nível de Referência: 2500 mm; Elevação da Base Ao Primeiro Nível de Referência: 0 mm; Elevação da Base Ao Piso de Origem: 0 mm; Elevação da Base À Cota Zero: 0 mm; Elevação da Base Ao Nível do Mar: 0 mm; Elevação da Base Ao Segundo Nível de Referência: 0 mm; Área da Superfície do Topo (Líquida): 0.024 m2; Área da Superfície da Borda (Líquida): 0.848 m2; Área da Superfície da Base (Líquida): 0.375 m2

# IfcWall: Alvenaria 140, Rebocada + Azulejo 160 (3)
In: Pavimento Térreo
Classification: Parede (Classificação Archicad); 3E 14 02 00 Parede (NBR 15965-5 3E)
Pset_WallCommon - AcousticRating: 0,00; LoadBearing: yes
BaseQuantities - Height: 2500 mm; Width: 160 mm
AC_Pset_RenovationAndPhasing - Renovation Status: Existing
ArchiCADQuantities - Número de Furos (Número de Aberturas Vazias): 0; Número de Pilares: 0; Volume dos Pilares: 0 m3; Altura Máxima da Camada da Parede na Face Interna: 2500 mm; Altura máxima da parede: 2500 mm; Altura Máxima da Camada da Parede na Face Externa: 2500 mm; Espessura da Camada de Ar: 0 mm; Espessura do Componente na Face Interna da Parede: 5 mm; Espessura do Componentena na Face Externa da Parede: 5 mm; Espessura da Parede na Terminação: 160 mm; Área de Superfície do Vão na Parede: 0 m2; Altura: 2500 mm; Largura: 160 mm; Elevação à Origem do Projeto: 0 mm; Elevação ao 1º Nível de Referência: 0 mm; Elevação ao 2º Nível de Referência: 0 mm; Elevação ao Nível do Mar: 0 mm; Elevação ao Piso: 0 mm; Afastamento do Piso de Origem: 0 mm; Afastamento do Topo: 0 mm; Espessura: 160 mm; Espessura da Camada de Isolamento: 0 mm; Elevação do Topo ao Primeiro Nível de Referência: 2500 mm; Elevação do Topo Ao Piso de Origem: 2500 mm; Elevação do Topo À Cota Zero: 2500 mm; Elevação do Topo Ao Nível do Mar: 2500 mm; Elevação do Topo Ao Segundo Nível de Referência: 2500 mm; Elevação da Base Ao Primeiro Nível de Referência: 0 mm; Elevação da Base Ao Piso de Origem: 0 mm; Elevação da Base À Cota Zero: 0 mm; Elevação da Base Ao Nível do Mar: 0 mm; Elevação da Base Ao Segundo Nível de Referência: 0 mm
